VERSION 5.7 ;
BUSBITCHARS "[]" ;
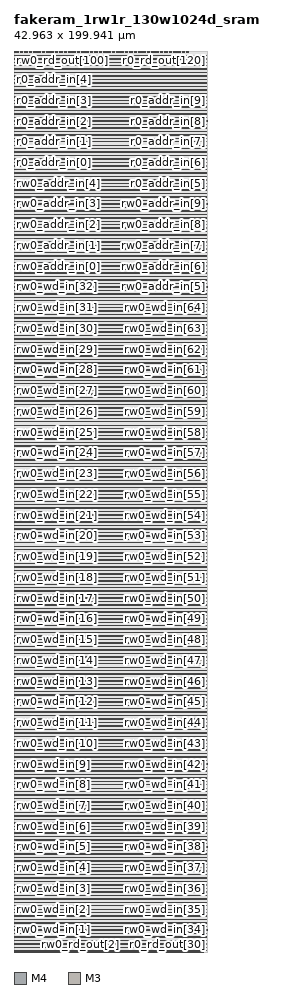
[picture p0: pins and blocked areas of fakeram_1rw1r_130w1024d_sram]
MACRO fakeram_1rw1r_130w1024d_sram
  FOREIGN fakeram_1rw1r_130w1024d_sram 0 0 ;
  SYMMETRY X Y R90 ;
  SIZE 42.963 BY 199.941 ;
  CLASS BLOCK ;
  PIN rw0_wd_in[0]
    DIRECTION INPUT ;
    USE SIGNAL ;
    SHAPE ABUTMENT ;
    PORT
      LAYER M4 ;
      RECT 0.000 0.276 0.072 0.300 ;
    END
  END rw0_wd_in[0]
  PIN rw0_wd_in[1]
    DIRECTION INPUT ;
    USE SIGNAL ;
    SHAPE ABUTMENT ;
    PORT
      LAYER M4 ;
      RECT 0.000 4.884 0.072 4.908 ;
    END
  END rw0_wd_in[1]
  PIN rw0_wd_in[2]
    DIRECTION INPUT ;
    USE SIGNAL ;
    SHAPE ABUTMENT ;
    PORT
      LAYER M4 ;
      RECT 0.000 9.492 0.072 9.516 ;
    END
  END rw0_wd_in[2]
  PIN rw0_wd_in[3]
    DIRECTION INPUT ;
    USE SIGNAL ;
    SHAPE ABUTMENT ;
    PORT
      LAYER M4 ;
      RECT 0.000 14.100 0.072 14.124 ;
    END
  END rw0_wd_in[3]
  PIN rw0_wd_in[4]
    DIRECTION INPUT ;
    USE SIGNAL ;
    SHAPE ABUTMENT ;
    PORT
      LAYER M4 ;
      RECT 0.000 18.708 0.072 18.732 ;
    END
  END rw0_wd_in[4]
  PIN rw0_wd_in[5]
    DIRECTION INPUT ;
    USE SIGNAL ;
    SHAPE ABUTMENT ;
    PORT
      LAYER M4 ;
      RECT 0.000 23.316 0.072 23.340 ;
    END
  END rw0_wd_in[5]
  PIN rw0_wd_in[6]
    DIRECTION INPUT ;
    USE SIGNAL ;
    SHAPE ABUTMENT ;
    PORT
      LAYER M4 ;
      RECT 0.000 27.924 0.072 27.948 ;
    END
  END rw0_wd_in[6]
  PIN rw0_wd_in[7]
    DIRECTION INPUT ;
    USE SIGNAL ;
    SHAPE ABUTMENT ;
    PORT
      LAYER M4 ;
      RECT 0.000 32.532 0.072 32.556 ;
    END
  END rw0_wd_in[7]
  PIN rw0_wd_in[8]
    DIRECTION INPUT ;
    USE SIGNAL ;
    SHAPE ABUTMENT ;
    PORT
      LAYER M4 ;
      RECT 0.000 37.140 0.072 37.164 ;
    END
  END rw0_wd_in[8]
  PIN rw0_wd_in[9]
    DIRECTION INPUT ;
    USE SIGNAL ;
    SHAPE ABUTMENT ;
    PORT
      LAYER M4 ;
      RECT 0.000 41.748 0.072 41.772 ;
    END
  END rw0_wd_in[9]
  PIN rw0_wd_in[10]
    DIRECTION INPUT ;
    USE SIGNAL ;
    SHAPE ABUTMENT ;
    PORT
      LAYER M4 ;
      RECT 0.000 46.356 0.072 46.380 ;
    END
  END rw0_wd_in[10]
  PIN rw0_wd_in[11]
    DIRECTION INPUT ;
    USE SIGNAL ;
    SHAPE ABUTMENT ;
    PORT
      LAYER M4 ;
      RECT 0.000 50.964 0.072 50.988 ;
    END
  END rw0_wd_in[11]
  PIN rw0_wd_in[12]
    DIRECTION INPUT ;
    USE SIGNAL ;
    SHAPE ABUTMENT ;
    PORT
      LAYER M4 ;
      RECT 0.000 55.572 0.072 55.596 ;
    END
  END rw0_wd_in[12]
  PIN rw0_wd_in[13]
    DIRECTION INPUT ;
    USE SIGNAL ;
    SHAPE ABUTMENT ;
    PORT
      LAYER M4 ;
      RECT 0.000 60.180 0.072 60.204 ;
    END
  END rw0_wd_in[13]
  PIN rw0_wd_in[14]
    DIRECTION INPUT ;
    USE SIGNAL ;
    SHAPE ABUTMENT ;
    PORT
      LAYER M4 ;
      RECT 0.000 64.788 0.072 64.812 ;
    END
  END rw0_wd_in[14]
  PIN rw0_wd_in[15]
    DIRECTION INPUT ;
    USE SIGNAL ;
    SHAPE ABUTMENT ;
    PORT
      LAYER M4 ;
      RECT 0.000 69.396 0.072 69.420 ;
    END
  END rw0_wd_in[15]
  PIN rw0_wd_in[16]
    DIRECTION INPUT ;
    USE SIGNAL ;
    SHAPE ABUTMENT ;
    PORT
      LAYER M4 ;
      RECT 0.000 74.004 0.072 74.028 ;
    END
  END rw0_wd_in[16]
  PIN rw0_wd_in[17]
    DIRECTION INPUT ;
    USE SIGNAL ;
    SHAPE ABUTMENT ;
    PORT
      LAYER M4 ;
      RECT 0.000 78.612 0.072 78.636 ;
    END
  END rw0_wd_in[17]
  PIN rw0_wd_in[18]
    DIRECTION INPUT ;
    USE SIGNAL ;
    SHAPE ABUTMENT ;
    PORT
      LAYER M4 ;
      RECT 0.000 83.220 0.072 83.244 ;
    END
  END rw0_wd_in[18]
  PIN rw0_wd_in[19]
    DIRECTION INPUT ;
    USE SIGNAL ;
    SHAPE ABUTMENT ;
    PORT
      LAYER M4 ;
      RECT 0.000 87.828 0.072 87.852 ;
    END
  END rw0_wd_in[19]
  PIN rw0_wd_in[20]
    DIRECTION INPUT ;
    USE SIGNAL ;
    SHAPE ABUTMENT ;
    PORT
      LAYER M4 ;
      RECT 0.000 92.436 0.072 92.460 ;
    END
  END rw0_wd_in[20]
  PIN rw0_wd_in[21]
    DIRECTION INPUT ;
    USE SIGNAL ;
    SHAPE ABUTMENT ;
    PORT
      LAYER M4 ;
      RECT 0.000 97.044 0.072 97.068 ;
    END
  END rw0_wd_in[21]
  PIN rw0_wd_in[22]
    DIRECTION INPUT ;
    USE SIGNAL ;
    SHAPE ABUTMENT ;
    PORT
      LAYER M4 ;
      RECT 0.000 101.652 0.072 101.676 ;
    END
  END rw0_wd_in[22]
  PIN rw0_wd_in[23]
    DIRECTION INPUT ;
    USE SIGNAL ;
    SHAPE ABUTMENT ;
    PORT
      LAYER M4 ;
      RECT 0.000 106.260 0.072 106.284 ;
    END
  END rw0_wd_in[23]
  PIN rw0_wd_in[24]
    DIRECTION INPUT ;
    USE SIGNAL ;
    SHAPE ABUTMENT ;
    PORT
      LAYER M4 ;
      RECT 0.000 110.868 0.072 110.892 ;
    END
  END rw0_wd_in[24]
  PIN rw0_wd_in[25]
    DIRECTION INPUT ;
    USE SIGNAL ;
    SHAPE ABUTMENT ;
    PORT
      LAYER M4 ;
      RECT 0.000 115.476 0.072 115.500 ;
    END
  END rw0_wd_in[25]
  PIN rw0_wd_in[26]
    DIRECTION INPUT ;
    USE SIGNAL ;
    SHAPE ABUTMENT ;
    PORT
      LAYER M4 ;
      RECT 0.000 120.084 0.072 120.108 ;
    END
  END rw0_wd_in[26]
  PIN rw0_wd_in[27]
    DIRECTION INPUT ;
    USE SIGNAL ;
    SHAPE ABUTMENT ;
    PORT
      LAYER M4 ;
      RECT 0.000 124.692 0.072 124.716 ;
    END
  END rw0_wd_in[27]
  PIN rw0_wd_in[28]
    DIRECTION INPUT ;
    USE SIGNAL ;
    SHAPE ABUTMENT ;
    PORT
      LAYER M4 ;
      RECT 0.000 129.300 0.072 129.324 ;
    END
  END rw0_wd_in[28]
  PIN rw0_wd_in[29]
    DIRECTION INPUT ;
    USE SIGNAL ;
    SHAPE ABUTMENT ;
    PORT
      LAYER M4 ;
      RECT 0.000 133.908 0.072 133.932 ;
    END
  END rw0_wd_in[29]
  PIN rw0_wd_in[30]
    DIRECTION INPUT ;
    USE SIGNAL ;
    SHAPE ABUTMENT ;
    PORT
      LAYER M4 ;
      RECT 0.000 138.516 0.072 138.540 ;
    END
  END rw0_wd_in[30]
  PIN rw0_wd_in[31]
    DIRECTION INPUT ;
    USE SIGNAL ;
    SHAPE ABUTMENT ;
    PORT
      LAYER M4 ;
      RECT 0.000 143.124 0.072 143.148 ;
    END
  END rw0_wd_in[31]
  PIN rw0_wd_in[32]
    DIRECTION INPUT ;
    USE SIGNAL ;
    SHAPE ABUTMENT ;
    PORT
      LAYER M4 ;
      RECT 0.000 147.732 0.072 147.756 ;
    END
  END rw0_wd_in[32]
  PIN rw0_wd_in[33]
    DIRECTION INPUT ;
    USE SIGNAL ;
    SHAPE ABUTMENT ;
    PORT
      LAYER M4 ;
      RECT 42.891 0.276 42.963 0.300 ;
    END
  END rw0_wd_in[33]
  PIN rw0_wd_in[34]
    DIRECTION INPUT ;
    USE SIGNAL ;
    SHAPE ABUTMENT ;
    PORT
      LAYER M4 ;
      RECT 42.891 4.884 42.963 4.908 ;
    END
  END rw0_wd_in[34]
  PIN rw0_wd_in[35]
    DIRECTION INPUT ;
    USE SIGNAL ;
    SHAPE ABUTMENT ;
    PORT
      LAYER M4 ;
      RECT 42.891 9.492 42.963 9.516 ;
    END
  END rw0_wd_in[35]
  PIN rw0_wd_in[36]
    DIRECTION INPUT ;
    USE SIGNAL ;
    SHAPE ABUTMENT ;
    PORT
      LAYER M4 ;
      RECT 42.891 14.100 42.963 14.124 ;
    END
  END rw0_wd_in[36]
  PIN rw0_wd_in[37]
    DIRECTION INPUT ;
    USE SIGNAL ;
    SHAPE ABUTMENT ;
    PORT
      LAYER M4 ;
      RECT 42.891 18.708 42.963 18.732 ;
    END
  END rw0_wd_in[37]
  PIN rw0_wd_in[38]
    DIRECTION INPUT ;
    USE SIGNAL ;
    SHAPE ABUTMENT ;
    PORT
      LAYER M4 ;
      RECT 42.891 23.316 42.963 23.340 ;
    END
  END rw0_wd_in[38]
  PIN rw0_wd_in[39]
    DIRECTION INPUT ;
    USE SIGNAL ;
    SHAPE ABUTMENT ;
    PORT
      LAYER M4 ;
      RECT 42.891 27.924 42.963 27.948 ;
    END
  END rw0_wd_in[39]
  PIN rw0_wd_in[40]
    DIRECTION INPUT ;
    USE SIGNAL ;
    SHAPE ABUTMENT ;
    PORT
      LAYER M4 ;
      RECT 42.891 32.532 42.963 32.556 ;
    END
  END rw0_wd_in[40]
  PIN rw0_wd_in[41]
    DIRECTION INPUT ;
    USE SIGNAL ;
    SHAPE ABUTMENT ;
    PORT
      LAYER M4 ;
      RECT 42.891 37.140 42.963 37.164 ;
    END
  END rw0_wd_in[41]
  PIN rw0_wd_in[42]
    DIRECTION INPUT ;
    USE SIGNAL ;
    SHAPE ABUTMENT ;
    PORT
      LAYER M4 ;
      RECT 42.891 41.748 42.963 41.772 ;
    END
  END rw0_wd_in[42]
  PIN rw0_wd_in[43]
    DIRECTION INPUT ;
    USE SIGNAL ;
    SHAPE ABUTMENT ;
    PORT
      LAYER M4 ;
      RECT 42.891 46.356 42.963 46.380 ;
    END
  END rw0_wd_in[43]
  PIN rw0_wd_in[44]
    DIRECTION INPUT ;
    USE SIGNAL ;
    SHAPE ABUTMENT ;
    PORT
      LAYER M4 ;
      RECT 42.891 50.964 42.963 50.988 ;
    END
  END rw0_wd_in[44]
  PIN rw0_wd_in[45]
    DIRECTION INPUT ;
    USE SIGNAL ;
    SHAPE ABUTMENT ;
    PORT
      LAYER M4 ;
      RECT 42.891 55.572 42.963 55.596 ;
    END
  END rw0_wd_in[45]
  PIN rw0_wd_in[46]
    DIRECTION INPUT ;
    USE SIGNAL ;
    SHAPE ABUTMENT ;
    PORT
      LAYER M4 ;
      RECT 42.891 60.180 42.963 60.204 ;
    END
  END rw0_wd_in[46]
  PIN rw0_wd_in[47]
    DIRECTION INPUT ;
    USE SIGNAL ;
    SHAPE ABUTMENT ;
    PORT
      LAYER M4 ;
      RECT 42.891 64.788 42.963 64.812 ;
    END
  END rw0_wd_in[47]
  PIN rw0_wd_in[48]
    DIRECTION INPUT ;
    USE SIGNAL ;
    SHAPE ABUTMENT ;
    PORT
      LAYER M4 ;
      RECT 42.891 69.396 42.963 69.420 ;
    END
  END rw0_wd_in[48]
  PIN rw0_wd_in[49]
    DIRECTION INPUT ;
    USE SIGNAL ;
    SHAPE ABUTMENT ;
    PORT
      LAYER M4 ;
      RECT 42.891 74.004 42.963 74.028 ;
    END
  END rw0_wd_in[49]
  PIN rw0_wd_in[50]
    DIRECTION INPUT ;
    USE SIGNAL ;
    SHAPE ABUTMENT ;
    PORT
      LAYER M4 ;
      RECT 42.891 78.612 42.963 78.636 ;
    END
  END rw0_wd_in[50]
  PIN rw0_wd_in[51]
    DIRECTION INPUT ;
    USE SIGNAL ;
    SHAPE ABUTMENT ;
    PORT
      LAYER M4 ;
      RECT 42.891 83.220 42.963 83.244 ;
    END
  END rw0_wd_in[51]
  PIN rw0_wd_in[52]
    DIRECTION INPUT ;
    USE SIGNAL ;
    SHAPE ABUTMENT ;
    PORT
      LAYER M4 ;
      RECT 42.891 87.828 42.963 87.852 ;
    END
  END rw0_wd_in[52]
  PIN rw0_wd_in[53]
    DIRECTION INPUT ;
    USE SIGNAL ;
    SHAPE ABUTMENT ;
    PORT
      LAYER M4 ;
      RECT 42.891 92.436 42.963 92.460 ;
    END
  END rw0_wd_in[53]
  PIN rw0_wd_in[54]
    DIRECTION INPUT ;
    USE SIGNAL ;
    SHAPE ABUTMENT ;
    PORT
      LAYER M4 ;
      RECT 42.891 97.044 42.963 97.068 ;
    END
  END rw0_wd_in[54]
  PIN rw0_wd_in[55]
    DIRECTION INPUT ;
    USE SIGNAL ;
    SHAPE ABUTMENT ;
    PORT
      LAYER M4 ;
      RECT 42.891 101.652 42.963 101.676 ;
    END
  END rw0_wd_in[55]
  PIN rw0_wd_in[56]
    DIRECTION INPUT ;
    USE SIGNAL ;
    SHAPE ABUTMENT ;
    PORT
      LAYER M4 ;
      RECT 42.891 106.260 42.963 106.284 ;
    END
  END rw0_wd_in[56]
  PIN rw0_wd_in[57]
    DIRECTION INPUT ;
    USE SIGNAL ;
    SHAPE ABUTMENT ;
    PORT
      LAYER M4 ;
      RECT 42.891 110.868 42.963 110.892 ;
    END
  END rw0_wd_in[57]
  PIN rw0_wd_in[58]
    DIRECTION INPUT ;
    USE SIGNAL ;
    SHAPE ABUTMENT ;
    PORT
      LAYER M4 ;
      RECT 42.891 115.476 42.963 115.500 ;
    END
  END rw0_wd_in[58]
  PIN rw0_wd_in[59]
    DIRECTION INPUT ;
    USE SIGNAL ;
    SHAPE ABUTMENT ;
    PORT
      LAYER M4 ;
      RECT 42.891 120.084 42.963 120.108 ;
    END
  END rw0_wd_in[59]
  PIN rw0_wd_in[60]
    DIRECTION INPUT ;
    USE SIGNAL ;
    SHAPE ABUTMENT ;
    PORT
      LAYER M4 ;
      RECT 42.891 124.692 42.963 124.716 ;
    END
  END rw0_wd_in[60]
  PIN rw0_wd_in[61]
    DIRECTION INPUT ;
    USE SIGNAL ;
    SHAPE ABUTMENT ;
    PORT
      LAYER M4 ;
      RECT 42.891 129.300 42.963 129.324 ;
    END
  END rw0_wd_in[61]
  PIN rw0_wd_in[62]
    DIRECTION INPUT ;
    USE SIGNAL ;
    SHAPE ABUTMENT ;
    PORT
      LAYER M4 ;
      RECT 42.891 133.908 42.963 133.932 ;
    END
  END rw0_wd_in[62]
  PIN rw0_wd_in[63]
    DIRECTION INPUT ;
    USE SIGNAL ;
    SHAPE ABUTMENT ;
    PORT
      LAYER M4 ;
      RECT 42.891 138.516 42.963 138.540 ;
    END
  END rw0_wd_in[63]
  PIN rw0_wd_in[64]
    DIRECTION INPUT ;
    USE SIGNAL ;
    SHAPE ABUTMENT ;
    PORT
      LAYER M4 ;
      RECT 42.891 143.124 42.963 143.148 ;
    END
  END rw0_wd_in[64]
  PIN rw0_wd_in[65]
    DIRECTION OUTPUT ;
    USE SIGNAL ;
    SHAPE ABUTMENT ;
    PORT
      LAYER M3 ;
      RECT 0.207 0.000 0.225 0.054 ;
    END
  END rw0_wd_in[65]
  PIN rw0_wd_in[66]
    DIRECTION OUTPUT ;
    USE SIGNAL ;
    SHAPE ABUTMENT ;
    PORT
      LAYER M3 ;
      RECT 0.423 0.000 0.441 0.054 ;
    END
  END rw0_wd_in[66]
  PIN rw0_wd_in[67]
    DIRECTION OUTPUT ;
    USE SIGNAL ;
    SHAPE ABUTMENT ;
    PORT
      LAYER M3 ;
      RECT 0.639 0.000 0.657 0.054 ;
    END
  END rw0_wd_in[67]
  PIN rw0_wd_in[68]
    DIRECTION OUTPUT ;
    USE SIGNAL ;
    SHAPE ABUTMENT ;
    PORT
      LAYER M3 ;
      RECT 0.855 0.000 0.873 0.054 ;
    END
  END rw0_wd_in[68]
  PIN rw0_wd_in[69]
    DIRECTION OUTPUT ;
    USE SIGNAL ;
    SHAPE ABUTMENT ;
    PORT
      LAYER M3 ;
      RECT 1.071 0.000 1.089 0.054 ;
    END
  END rw0_wd_in[69]
  PIN rw0_wd_in[70]
    DIRECTION OUTPUT ;
    USE SIGNAL ;
    SHAPE ABUTMENT ;
    PORT
      LAYER M3 ;
      RECT 1.287 0.000 1.305 0.054 ;
    END
  END rw0_wd_in[70]
  PIN rw0_wd_in[71]
    DIRECTION OUTPUT ;
    USE SIGNAL ;
    SHAPE ABUTMENT ;
    PORT
      LAYER M3 ;
      RECT 1.503 0.000 1.521 0.054 ;
    END
  END rw0_wd_in[71]
  PIN rw0_wd_in[72]
    DIRECTION OUTPUT ;
    USE SIGNAL ;
    SHAPE ABUTMENT ;
    PORT
      LAYER M3 ;
      RECT 1.719 0.000 1.737 0.054 ;
    END
  END rw0_wd_in[72]
  PIN rw0_wd_in[73]
    DIRECTION OUTPUT ;
    USE SIGNAL ;
    SHAPE ABUTMENT ;
    PORT
      LAYER M3 ;
      RECT 1.935 0.000 1.953 0.054 ;
    END
  END rw0_wd_in[73]
  PIN rw0_wd_in[74]
    DIRECTION OUTPUT ;
    USE SIGNAL ;
    SHAPE ABUTMENT ;
    PORT
      LAYER M3 ;
      RECT 2.151 0.000 2.169 0.054 ;
    END
  END rw0_wd_in[74]
  PIN rw0_wd_in[75]
    DIRECTION OUTPUT ;
    USE SIGNAL ;
    SHAPE ABUTMENT ;
    PORT
      LAYER M3 ;
      RECT 2.367 0.000 2.385 0.054 ;
    END
  END rw0_wd_in[75]
  PIN rw0_wd_in[76]
    DIRECTION OUTPUT ;
    USE SIGNAL ;
    SHAPE ABUTMENT ;
    PORT
      LAYER M3 ;
      RECT 2.583 0.000 2.601 0.054 ;
    END
  END rw0_wd_in[76]
  PIN rw0_wd_in[77]
    DIRECTION OUTPUT ;
    USE SIGNAL ;
    SHAPE ABUTMENT ;
    PORT
      LAYER M3 ;
      RECT 2.799 0.000 2.817 0.054 ;
    END
  END rw0_wd_in[77]
  PIN rw0_wd_in[78]
    DIRECTION OUTPUT ;
    USE SIGNAL ;
    SHAPE ABUTMENT ;
    PORT
      LAYER M3 ;
      RECT 3.015 0.000 3.033 0.054 ;
    END
  END rw0_wd_in[78]
  PIN rw0_wd_in[79]
    DIRECTION OUTPUT ;
    USE SIGNAL ;
    SHAPE ABUTMENT ;
    PORT
      LAYER M3 ;
      RECT 3.231 0.000 3.249 0.054 ;
    END
  END rw0_wd_in[79]
  PIN rw0_wd_in[80]
    DIRECTION OUTPUT ;
    USE SIGNAL ;
    SHAPE ABUTMENT ;
    PORT
      LAYER M3 ;
      RECT 3.447 0.000 3.465 0.054 ;
    END
  END rw0_wd_in[80]
  PIN rw0_wd_in[81]
    DIRECTION OUTPUT ;
    USE SIGNAL ;
    SHAPE ABUTMENT ;
    PORT
      LAYER M3 ;
      RECT 3.663 0.000 3.681 0.054 ;
    END
  END rw0_wd_in[81]
  PIN rw0_wd_in[82]
    DIRECTION OUTPUT ;
    USE SIGNAL ;
    SHAPE ABUTMENT ;
    PORT
      LAYER M3 ;
      RECT 3.879 0.000 3.897 0.054 ;
    END
  END rw0_wd_in[82]
  PIN rw0_wd_in[83]
    DIRECTION OUTPUT ;
    USE SIGNAL ;
    SHAPE ABUTMENT ;
    PORT
      LAYER M3 ;
      RECT 4.095 0.000 4.113 0.054 ;
    END
  END rw0_wd_in[83]
  PIN rw0_wd_in[84]
    DIRECTION OUTPUT ;
    USE SIGNAL ;
    SHAPE ABUTMENT ;
    PORT
      LAYER M3 ;
      RECT 4.311 0.000 4.329 0.054 ;
    END
  END rw0_wd_in[84]
  PIN rw0_wd_in[85]
    DIRECTION OUTPUT ;
    USE SIGNAL ;
    SHAPE ABUTMENT ;
    PORT
      LAYER M3 ;
      RECT 4.527 0.000 4.545 0.054 ;
    END
  END rw0_wd_in[85]
  PIN rw0_wd_in[86]
    DIRECTION OUTPUT ;
    USE SIGNAL ;
    SHAPE ABUTMENT ;
    PORT
      LAYER M3 ;
      RECT 4.743 0.000 4.761 0.054 ;
    END
  END rw0_wd_in[86]
  PIN rw0_wd_in[87]
    DIRECTION OUTPUT ;
    USE SIGNAL ;
    SHAPE ABUTMENT ;
    PORT
      LAYER M3 ;
      RECT 4.959 0.000 4.977 0.054 ;
    END
  END rw0_wd_in[87]
  PIN rw0_wd_in[88]
    DIRECTION OUTPUT ;
    USE SIGNAL ;
    SHAPE ABUTMENT ;
    PORT
      LAYER M3 ;
      RECT 5.175 0.000 5.193 0.054 ;
    END
  END rw0_wd_in[88]
  PIN rw0_wd_in[89]
    DIRECTION OUTPUT ;
    USE SIGNAL ;
    SHAPE ABUTMENT ;
    PORT
      LAYER M3 ;
      RECT 5.391 0.000 5.409 0.054 ;
    END
  END rw0_wd_in[89]
  PIN rw0_wd_in[90]
    DIRECTION OUTPUT ;
    USE SIGNAL ;
    SHAPE ABUTMENT ;
    PORT
      LAYER M3 ;
      RECT 5.607 0.000 5.625 0.054 ;
    END
  END rw0_wd_in[90]
  PIN rw0_wd_in[91]
    DIRECTION OUTPUT ;
    USE SIGNAL ;
    SHAPE ABUTMENT ;
    PORT
      LAYER M3 ;
      RECT 5.823 0.000 5.841 0.054 ;
    END
  END rw0_wd_in[91]
  PIN rw0_wd_in[92]
    DIRECTION OUTPUT ;
    USE SIGNAL ;
    SHAPE ABUTMENT ;
    PORT
      LAYER M3 ;
      RECT 6.039 0.000 6.057 0.054 ;
    END
  END rw0_wd_in[92]
  PIN rw0_wd_in[93]
    DIRECTION OUTPUT ;
    USE SIGNAL ;
    SHAPE ABUTMENT ;
    PORT
      LAYER M3 ;
      RECT 6.255 0.000 6.273 0.054 ;
    END
  END rw0_wd_in[93]
  PIN rw0_wd_in[94]
    DIRECTION OUTPUT ;
    USE SIGNAL ;
    SHAPE ABUTMENT ;
    PORT
      LAYER M3 ;
      RECT 6.471 0.000 6.489 0.054 ;
    END
  END rw0_wd_in[94]
  PIN rw0_wd_in[95]
    DIRECTION OUTPUT ;
    USE SIGNAL ;
    SHAPE ABUTMENT ;
    PORT
      LAYER M3 ;
      RECT 6.687 0.000 6.705 0.054 ;
    END
  END rw0_wd_in[95]
  PIN rw0_wd_in[96]
    DIRECTION OUTPUT ;
    USE SIGNAL ;
    SHAPE ABUTMENT ;
    PORT
      LAYER M3 ;
      RECT 6.903 0.000 6.921 0.054 ;
    END
  END rw0_wd_in[96]
  PIN rw0_wd_in[97]
    DIRECTION OUTPUT ;
    USE SIGNAL ;
    SHAPE ABUTMENT ;
    PORT
      LAYER M3 ;
      RECT 7.119 0.000 7.137 0.054 ;
    END
  END rw0_wd_in[97]
  PIN rw0_wd_in[98]
    DIRECTION OUTPUT ;
    USE SIGNAL ;
    SHAPE ABUTMENT ;
    PORT
      LAYER M3 ;
      RECT 7.335 0.000 7.353 0.054 ;
    END
  END rw0_wd_in[98]
  PIN rw0_wd_in[99]
    DIRECTION OUTPUT ;
    USE SIGNAL ;
    SHAPE ABUTMENT ;
    PORT
      LAYER M3 ;
      RECT 7.551 0.000 7.569 0.054 ;
    END
  END rw0_wd_in[99]
  PIN rw0_wd_in[100]
    DIRECTION OUTPUT ;
    USE SIGNAL ;
    SHAPE ABUTMENT ;
    PORT
      LAYER M3 ;
      RECT 7.767 0.000 7.785 0.054 ;
    END
  END rw0_wd_in[100]
  PIN rw0_wd_in[101]
    DIRECTION OUTPUT ;
    USE SIGNAL ;
    SHAPE ABUTMENT ;
    PORT
      LAYER M3 ;
      RECT 7.983 0.000 8.001 0.054 ;
    END
  END rw0_wd_in[101]
  PIN rw0_wd_in[102]
    DIRECTION OUTPUT ;
    USE SIGNAL ;
    SHAPE ABUTMENT ;
    PORT
      LAYER M3 ;
      RECT 8.199 0.000 8.217 0.054 ;
    END
  END rw0_wd_in[102]
  PIN rw0_wd_in[103]
    DIRECTION OUTPUT ;
    USE SIGNAL ;
    SHAPE ABUTMENT ;
    PORT
      LAYER M3 ;
      RECT 8.415 0.000 8.433 0.054 ;
    END
  END rw0_wd_in[103]
  PIN rw0_wd_in[104]
    DIRECTION OUTPUT ;
    USE SIGNAL ;
    SHAPE ABUTMENT ;
    PORT
      LAYER M3 ;
      RECT 8.631 0.000 8.649 0.054 ;
    END
  END rw0_wd_in[104]
  PIN rw0_wd_in[105]
    DIRECTION OUTPUT ;
    USE SIGNAL ;
    SHAPE ABUTMENT ;
    PORT
      LAYER M3 ;
      RECT 8.847 0.000 8.865 0.054 ;
    END
  END rw0_wd_in[105]
  PIN rw0_wd_in[106]
    DIRECTION OUTPUT ;
    USE SIGNAL ;
    SHAPE ABUTMENT ;
    PORT
      LAYER M3 ;
      RECT 9.063 0.000 9.081 0.054 ;
    END
  END rw0_wd_in[106]
  PIN rw0_wd_in[107]
    DIRECTION OUTPUT ;
    USE SIGNAL ;
    SHAPE ABUTMENT ;
    PORT
      LAYER M3 ;
      RECT 9.279 0.000 9.297 0.054 ;
    END
  END rw0_wd_in[107]
  PIN rw0_wd_in[108]
    DIRECTION OUTPUT ;
    USE SIGNAL ;
    SHAPE ABUTMENT ;
    PORT
      LAYER M3 ;
      RECT 9.495 0.000 9.513 0.054 ;
    END
  END rw0_wd_in[108]
  PIN rw0_wd_in[109]
    DIRECTION OUTPUT ;
    USE SIGNAL ;
    SHAPE ABUTMENT ;
    PORT
      LAYER M3 ;
      RECT 9.711 0.000 9.729 0.054 ;
    END
  END rw0_wd_in[109]
  PIN rw0_wd_in[110]
    DIRECTION OUTPUT ;
    USE SIGNAL ;
    SHAPE ABUTMENT ;
    PORT
      LAYER M3 ;
      RECT 9.927 0.000 9.945 0.054 ;
    END
  END rw0_wd_in[110]
  PIN rw0_wd_in[111]
    DIRECTION OUTPUT ;
    USE SIGNAL ;
    SHAPE ABUTMENT ;
    PORT
      LAYER M3 ;
      RECT 10.143 0.000 10.161 0.054 ;
    END
  END rw0_wd_in[111]
  PIN rw0_wd_in[112]
    DIRECTION OUTPUT ;
    USE SIGNAL ;
    SHAPE ABUTMENT ;
    PORT
      LAYER M3 ;
      RECT 10.359 0.000 10.377 0.054 ;
    END
  END rw0_wd_in[112]
  PIN rw0_wd_in[113]
    DIRECTION OUTPUT ;
    USE SIGNAL ;
    SHAPE ABUTMENT ;
    PORT
      LAYER M3 ;
      RECT 10.575 0.000 10.593 0.054 ;
    END
  END rw0_wd_in[113]
  PIN rw0_wd_in[114]
    DIRECTION OUTPUT ;
    USE SIGNAL ;
    SHAPE ABUTMENT ;
    PORT
      LAYER M3 ;
      RECT 10.791 0.000 10.809 0.054 ;
    END
  END rw0_wd_in[114]
  PIN rw0_wd_in[115]
    DIRECTION OUTPUT ;
    USE SIGNAL ;
    SHAPE ABUTMENT ;
    PORT
      LAYER M3 ;
      RECT 11.007 0.000 11.025 0.054 ;
    END
  END rw0_wd_in[115]
  PIN rw0_wd_in[116]
    DIRECTION OUTPUT ;
    USE SIGNAL ;
    SHAPE ABUTMENT ;
    PORT
      LAYER M3 ;
      RECT 11.223 0.000 11.241 0.054 ;
    END
  END rw0_wd_in[116]
  PIN rw0_wd_in[117]
    DIRECTION OUTPUT ;
    USE SIGNAL ;
    SHAPE ABUTMENT ;
    PORT
      LAYER M3 ;
      RECT 11.439 0.000 11.457 0.054 ;
    END
  END rw0_wd_in[117]
  PIN rw0_wd_in[118]
    DIRECTION OUTPUT ;
    USE SIGNAL ;
    SHAPE ABUTMENT ;
    PORT
      LAYER M3 ;
      RECT 11.655 0.000 11.673 0.054 ;
    END
  END rw0_wd_in[118]
  PIN rw0_wd_in[119]
    DIRECTION OUTPUT ;
    USE SIGNAL ;
    SHAPE ABUTMENT ;
    PORT
      LAYER M3 ;
      RECT 11.871 0.000 11.889 0.054 ;
    END
  END rw0_wd_in[119]
  PIN rw0_wd_in[120]
    DIRECTION OUTPUT ;
    USE SIGNAL ;
    SHAPE ABUTMENT ;
    PORT
      LAYER M3 ;
      RECT 12.087 0.000 12.105 0.054 ;
    END
  END rw0_wd_in[120]
  PIN rw0_wd_in[121]
    DIRECTION OUTPUT ;
    USE SIGNAL ;
    SHAPE ABUTMENT ;
    PORT
      LAYER M3 ;
      RECT 12.303 0.000 12.321 0.054 ;
    END
  END rw0_wd_in[121]
  PIN rw0_wd_in[122]
    DIRECTION OUTPUT ;
    USE SIGNAL ;
    SHAPE ABUTMENT ;
    PORT
      LAYER M3 ;
      RECT 12.519 0.000 12.537 0.054 ;
    END
  END rw0_wd_in[122]
  PIN rw0_wd_in[123]
    DIRECTION OUTPUT ;
    USE SIGNAL ;
    SHAPE ABUTMENT ;
    PORT
      LAYER M3 ;
      RECT 12.735 0.000 12.753 0.054 ;
    END
  END rw0_wd_in[123]
  PIN rw0_wd_in[124]
    DIRECTION OUTPUT ;
    USE SIGNAL ;
    SHAPE ABUTMENT ;
    PORT
      LAYER M3 ;
      RECT 12.951 0.000 12.969 0.054 ;
    END
  END rw0_wd_in[124]
  PIN rw0_wd_in[125]
    DIRECTION OUTPUT ;
    USE SIGNAL ;
    SHAPE ABUTMENT ;
    PORT
      LAYER M3 ;
      RECT 13.167 0.000 13.185 0.054 ;
    END
  END rw0_wd_in[125]
  PIN rw0_wd_in[126]
    DIRECTION OUTPUT ;
    USE SIGNAL ;
    SHAPE ABUTMENT ;
    PORT
      LAYER M3 ;
      RECT 13.383 0.000 13.401 0.054 ;
    END
  END rw0_wd_in[126]
  PIN rw0_wd_in[127]
    DIRECTION OUTPUT ;
    USE SIGNAL ;
    SHAPE ABUTMENT ;
    PORT
      LAYER M3 ;
      RECT 13.599 0.000 13.617 0.054 ;
    END
  END rw0_wd_in[127]
  PIN rw0_wd_in[128]
    DIRECTION OUTPUT ;
    USE SIGNAL ;
    SHAPE ABUTMENT ;
    PORT
      LAYER M3 ;
      RECT 13.815 0.000 13.833 0.054 ;
    END
  END rw0_wd_in[128]
  PIN rw0_wd_in[129]
    DIRECTION OUTPUT ;
    USE SIGNAL ;
    SHAPE ABUTMENT ;
    PORT
      LAYER M3 ;
      RECT 14.031 0.000 14.049 0.054 ;
    END
  END rw0_wd_in[129]
  PIN rw0_rd_out[0]
    DIRECTION OUTPUT ;
    USE SIGNAL ;
    SHAPE ABUTMENT ;
    PORT
      LAYER M3 ;
      RECT 14.247 0.000 14.265 0.054 ;
    END
  END rw0_rd_out[0]
  PIN rw0_rd_out[1]
    DIRECTION OUTPUT ;
    USE SIGNAL ;
    SHAPE ABUTMENT ;
    PORT
      LAYER M3 ;
      RECT 14.463 0.000 14.481 0.054 ;
    END
  END rw0_rd_out[1]
  PIN rw0_rd_out[2]
    DIRECTION OUTPUT ;
    USE SIGNAL ;
    SHAPE ABUTMENT ;
    PORT
      LAYER M3 ;
      RECT 14.679 0.000 14.697 0.054 ;
    END
  END rw0_rd_out[2]
  PIN rw0_rd_out[3]
    DIRECTION OUTPUT ;
    USE SIGNAL ;
    SHAPE ABUTMENT ;
    PORT
      LAYER M3 ;
      RECT 14.895 0.000 14.913 0.054 ;
    END
  END rw0_rd_out[3]
  PIN rw0_rd_out[4]
    DIRECTION OUTPUT ;
    USE SIGNAL ;
    SHAPE ABUTMENT ;
    PORT
      LAYER M3 ;
      RECT 15.111 0.000 15.129 0.054 ;
    END
  END rw0_rd_out[4]
  PIN rw0_rd_out[5]
    DIRECTION OUTPUT ;
    USE SIGNAL ;
    SHAPE ABUTMENT ;
    PORT
      LAYER M3 ;
      RECT 15.327 0.000 15.345 0.054 ;
    END
  END rw0_rd_out[5]
  PIN rw0_rd_out[6]
    DIRECTION OUTPUT ;
    USE SIGNAL ;
    SHAPE ABUTMENT ;
    PORT
      LAYER M3 ;
      RECT 15.543 0.000 15.561 0.054 ;
    END
  END rw0_rd_out[6]
  PIN rw0_rd_out[7]
    DIRECTION OUTPUT ;
    USE SIGNAL ;
    SHAPE ABUTMENT ;
    PORT
      LAYER M3 ;
      RECT 15.759 0.000 15.777 0.054 ;
    END
  END rw0_rd_out[7]
  PIN rw0_rd_out[8]
    DIRECTION OUTPUT ;
    USE SIGNAL ;
    SHAPE ABUTMENT ;
    PORT
      LAYER M3 ;
      RECT 15.975 0.000 15.993 0.054 ;
    END
  END rw0_rd_out[8]
  PIN rw0_rd_out[9]
    DIRECTION OUTPUT ;
    USE SIGNAL ;
    SHAPE ABUTMENT ;
    PORT
      LAYER M3 ;
      RECT 16.191 0.000 16.209 0.054 ;
    END
  END rw0_rd_out[9]
  PIN rw0_rd_out[10]
    DIRECTION OUTPUT ;
    USE SIGNAL ;
    SHAPE ABUTMENT ;
    PORT
      LAYER M3 ;
      RECT 16.407 0.000 16.425 0.054 ;
    END
  END rw0_rd_out[10]
  PIN rw0_rd_out[11]
    DIRECTION OUTPUT ;
    USE SIGNAL ;
    SHAPE ABUTMENT ;
    PORT
      LAYER M3 ;
      RECT 16.623 0.000 16.641 0.054 ;
    END
  END rw0_rd_out[11]
  PIN rw0_rd_out[12]
    DIRECTION OUTPUT ;
    USE SIGNAL ;
    SHAPE ABUTMENT ;
    PORT
      LAYER M3 ;
      RECT 16.839 0.000 16.857 0.054 ;
    END
  END rw0_rd_out[12]
  PIN rw0_rd_out[13]
    DIRECTION OUTPUT ;
    USE SIGNAL ;
    SHAPE ABUTMENT ;
    PORT
      LAYER M3 ;
      RECT 17.055 0.000 17.073 0.054 ;
    END
  END rw0_rd_out[13]
  PIN rw0_rd_out[14]
    DIRECTION OUTPUT ;
    USE SIGNAL ;
    SHAPE ABUTMENT ;
    PORT
      LAYER M3 ;
      RECT 17.271 0.000 17.289 0.054 ;
    END
  END rw0_rd_out[14]
  PIN rw0_rd_out[15]
    DIRECTION OUTPUT ;
    USE SIGNAL ;
    SHAPE ABUTMENT ;
    PORT
      LAYER M3 ;
      RECT 17.487 0.000 17.505 0.054 ;
    END
  END rw0_rd_out[15]
  PIN rw0_rd_out[16]
    DIRECTION OUTPUT ;
    USE SIGNAL ;
    SHAPE ABUTMENT ;
    PORT
      LAYER M3 ;
      RECT 17.703 0.000 17.721 0.054 ;
    END
  END rw0_rd_out[16]
  PIN rw0_rd_out[17]
    DIRECTION OUTPUT ;
    USE SIGNAL ;
    SHAPE ABUTMENT ;
    PORT
      LAYER M3 ;
      RECT 17.919 0.000 17.937 0.054 ;
    END
  END rw0_rd_out[17]
  PIN rw0_rd_out[18]
    DIRECTION OUTPUT ;
    USE SIGNAL ;
    SHAPE ABUTMENT ;
    PORT
      LAYER M3 ;
      RECT 18.135 0.000 18.153 0.054 ;
    END
  END rw0_rd_out[18]
  PIN rw0_rd_out[19]
    DIRECTION OUTPUT ;
    USE SIGNAL ;
    SHAPE ABUTMENT ;
    PORT
      LAYER M3 ;
      RECT 18.351 0.000 18.369 0.054 ;
    END
  END rw0_rd_out[19]
  PIN rw0_rd_out[20]
    DIRECTION OUTPUT ;
    USE SIGNAL ;
    SHAPE ABUTMENT ;
    PORT
      LAYER M3 ;
      RECT 18.567 0.000 18.585 0.054 ;
    END
  END rw0_rd_out[20]
  PIN rw0_rd_out[21]
    DIRECTION OUTPUT ;
    USE SIGNAL ;
    SHAPE ABUTMENT ;
    PORT
      LAYER M3 ;
      RECT 18.783 0.000 18.801 0.054 ;
    END
  END rw0_rd_out[21]
  PIN rw0_rd_out[22]
    DIRECTION OUTPUT ;
    USE SIGNAL ;
    SHAPE ABUTMENT ;
    PORT
      LAYER M3 ;
      RECT 18.999 0.000 19.017 0.054 ;
    END
  END rw0_rd_out[22]
  PIN rw0_rd_out[23]
    DIRECTION OUTPUT ;
    USE SIGNAL ;
    SHAPE ABUTMENT ;
    PORT
      LAYER M3 ;
      RECT 19.215 0.000 19.233 0.054 ;
    END
  END rw0_rd_out[23]
  PIN rw0_rd_out[24]
    DIRECTION OUTPUT ;
    USE SIGNAL ;
    SHAPE ABUTMENT ;
    PORT
      LAYER M3 ;
      RECT 19.431 0.000 19.449 0.054 ;
    END
  END rw0_rd_out[24]
  PIN rw0_rd_out[25]
    DIRECTION OUTPUT ;
    USE SIGNAL ;
    SHAPE ABUTMENT ;
    PORT
      LAYER M3 ;
      RECT 19.647 0.000 19.665 0.054 ;
    END
  END rw0_rd_out[25]
  PIN rw0_rd_out[26]
    DIRECTION OUTPUT ;
    USE SIGNAL ;
    SHAPE ABUTMENT ;
    PORT
      LAYER M3 ;
      RECT 19.863 0.000 19.881 0.054 ;
    END
  END rw0_rd_out[26]
  PIN rw0_rd_out[27]
    DIRECTION OUTPUT ;
    USE SIGNAL ;
    SHAPE ABUTMENT ;
    PORT
      LAYER M3 ;
      RECT 20.079 0.000 20.097 0.054 ;
    END
  END rw0_rd_out[27]
  PIN rw0_rd_out[28]
    DIRECTION OUTPUT ;
    USE SIGNAL ;
    SHAPE ABUTMENT ;
    PORT
      LAYER M3 ;
      RECT 20.295 0.000 20.313 0.054 ;
    END
  END rw0_rd_out[28]
  PIN rw0_rd_out[29]
    DIRECTION OUTPUT ;
    USE SIGNAL ;
    SHAPE ABUTMENT ;
    PORT
      LAYER M3 ;
      RECT 20.511 0.000 20.529 0.054 ;
    END
  END rw0_rd_out[29]
  PIN rw0_rd_out[30]
    DIRECTION OUTPUT ;
    USE SIGNAL ;
    SHAPE ABUTMENT ;
    PORT
      LAYER M3 ;
      RECT 20.727 0.000 20.745 0.054 ;
    END
  END rw0_rd_out[30]
  PIN rw0_rd_out[31]
    DIRECTION OUTPUT ;
    USE SIGNAL ;
    SHAPE ABUTMENT ;
    PORT
      LAYER M3 ;
      RECT 20.943 0.000 20.961 0.054 ;
    END
  END rw0_rd_out[31]
  PIN rw0_rd_out[32]
    DIRECTION OUTPUT ;
    USE SIGNAL ;
    SHAPE ABUTMENT ;
    PORT
      LAYER M3 ;
      RECT 21.159 0.000 21.177 0.054 ;
    END
  END rw0_rd_out[32]
  PIN rw0_rd_out[33]
    DIRECTION OUTPUT ;
    USE SIGNAL ;
    SHAPE ABUTMENT ;
    PORT
      LAYER M3 ;
      RECT 21.375 0.000 21.393 0.054 ;
    END
  END rw0_rd_out[33]
  PIN rw0_rd_out[34]
    DIRECTION OUTPUT ;
    USE SIGNAL ;
    SHAPE ABUTMENT ;
    PORT
      LAYER M3 ;
      RECT 21.591 0.000 21.609 0.054 ;
    END
  END rw0_rd_out[34]
  PIN rw0_rd_out[35]
    DIRECTION OUTPUT ;
    USE SIGNAL ;
    SHAPE ABUTMENT ;
    PORT
      LAYER M3 ;
      RECT 21.807 0.000 21.825 0.054 ;
    END
  END rw0_rd_out[35]
  PIN rw0_rd_out[36]
    DIRECTION OUTPUT ;
    USE SIGNAL ;
    SHAPE ABUTMENT ;
    PORT
      LAYER M3 ;
      RECT 22.023 0.000 22.041 0.054 ;
    END
  END rw0_rd_out[36]
  PIN rw0_rd_out[37]
    DIRECTION OUTPUT ;
    USE SIGNAL ;
    SHAPE ABUTMENT ;
    PORT
      LAYER M3 ;
      RECT 22.239 0.000 22.257 0.054 ;
    END
  END rw0_rd_out[37]
  PIN rw0_rd_out[38]
    DIRECTION OUTPUT ;
    USE SIGNAL ;
    SHAPE ABUTMENT ;
    PORT
      LAYER M3 ;
      RECT 22.455 0.000 22.473 0.054 ;
    END
  END rw0_rd_out[38]
  PIN rw0_rd_out[39]
    DIRECTION OUTPUT ;
    USE SIGNAL ;
    SHAPE ABUTMENT ;
    PORT
      LAYER M3 ;
      RECT 22.671 0.000 22.689 0.054 ;
    END
  END rw0_rd_out[39]
  PIN rw0_rd_out[40]
    DIRECTION OUTPUT ;
    USE SIGNAL ;
    SHAPE ABUTMENT ;
    PORT
      LAYER M3 ;
      RECT 22.887 0.000 22.905 0.054 ;
    END
  END rw0_rd_out[40]
  PIN rw0_rd_out[41]
    DIRECTION OUTPUT ;
    USE SIGNAL ;
    SHAPE ABUTMENT ;
    PORT
      LAYER M3 ;
      RECT 23.103 0.000 23.121 0.054 ;
    END
  END rw0_rd_out[41]
  PIN rw0_rd_out[42]
    DIRECTION OUTPUT ;
    USE SIGNAL ;
    SHAPE ABUTMENT ;
    PORT
      LAYER M3 ;
      RECT 23.319 0.000 23.337 0.054 ;
    END
  END rw0_rd_out[42]
  PIN rw0_rd_out[43]
    DIRECTION OUTPUT ;
    USE SIGNAL ;
    SHAPE ABUTMENT ;
    PORT
      LAYER M3 ;
      RECT 23.535 0.000 23.553 0.054 ;
    END
  END rw0_rd_out[43]
  PIN rw0_rd_out[44]
    DIRECTION OUTPUT ;
    USE SIGNAL ;
    SHAPE ABUTMENT ;
    PORT
      LAYER M3 ;
      RECT 23.751 0.000 23.769 0.054 ;
    END
  END rw0_rd_out[44]
  PIN rw0_rd_out[45]
    DIRECTION OUTPUT ;
    USE SIGNAL ;
    SHAPE ABUTMENT ;
    PORT
      LAYER M3 ;
      RECT 23.967 0.000 23.985 0.054 ;
    END
  END rw0_rd_out[45]
  PIN rw0_rd_out[46]
    DIRECTION OUTPUT ;
    USE SIGNAL ;
    SHAPE ABUTMENT ;
    PORT
      LAYER M3 ;
      RECT 24.183 0.000 24.201 0.054 ;
    END
  END rw0_rd_out[46]
  PIN rw0_rd_out[47]
    DIRECTION OUTPUT ;
    USE SIGNAL ;
    SHAPE ABUTMENT ;
    PORT
      LAYER M3 ;
      RECT 24.399 0.000 24.417 0.054 ;
    END
  END rw0_rd_out[47]
  PIN rw0_rd_out[48]
    DIRECTION OUTPUT ;
    USE SIGNAL ;
    SHAPE ABUTMENT ;
    PORT
      LAYER M3 ;
      RECT 24.615 0.000 24.633 0.054 ;
    END
  END rw0_rd_out[48]
  PIN rw0_rd_out[49]
    DIRECTION OUTPUT ;
    USE SIGNAL ;
    SHAPE ABUTMENT ;
    PORT
      LAYER M3 ;
      RECT 24.831 0.000 24.849 0.054 ;
    END
  END rw0_rd_out[49]
  PIN rw0_rd_out[50]
    DIRECTION OUTPUT ;
    USE SIGNAL ;
    SHAPE ABUTMENT ;
    PORT
      LAYER M3 ;
      RECT 25.047 0.000 25.065 0.054 ;
    END
  END rw0_rd_out[50]
  PIN rw0_rd_out[51]
    DIRECTION OUTPUT ;
    USE SIGNAL ;
    SHAPE ABUTMENT ;
    PORT
      LAYER M3 ;
      RECT 25.263 0.000 25.281 0.054 ;
    END
  END rw0_rd_out[51]
  PIN rw0_rd_out[52]
    DIRECTION OUTPUT ;
    USE SIGNAL ;
    SHAPE ABUTMENT ;
    PORT
      LAYER M3 ;
      RECT 25.479 0.000 25.497 0.054 ;
    END
  END rw0_rd_out[52]
  PIN rw0_rd_out[53]
    DIRECTION OUTPUT ;
    USE SIGNAL ;
    SHAPE ABUTMENT ;
    PORT
      LAYER M3 ;
      RECT 25.695 0.000 25.713 0.054 ;
    END
  END rw0_rd_out[53]
  PIN rw0_rd_out[54]
    DIRECTION OUTPUT ;
    USE SIGNAL ;
    SHAPE ABUTMENT ;
    PORT
      LAYER M3 ;
      RECT 25.911 0.000 25.929 0.054 ;
    END
  END rw0_rd_out[54]
  PIN rw0_rd_out[55]
    DIRECTION OUTPUT ;
    USE SIGNAL ;
    SHAPE ABUTMENT ;
    PORT
      LAYER M3 ;
      RECT 26.127 0.000 26.145 0.054 ;
    END
  END rw0_rd_out[55]
  PIN rw0_rd_out[56]
    DIRECTION OUTPUT ;
    USE SIGNAL ;
    SHAPE ABUTMENT ;
    PORT
      LAYER M3 ;
      RECT 26.343 0.000 26.361 0.054 ;
    END
  END rw0_rd_out[56]
  PIN rw0_rd_out[57]
    DIRECTION OUTPUT ;
    USE SIGNAL ;
    SHAPE ABUTMENT ;
    PORT
      LAYER M3 ;
      RECT 26.559 0.000 26.577 0.054 ;
    END
  END rw0_rd_out[57]
  PIN rw0_rd_out[58]
    DIRECTION OUTPUT ;
    USE SIGNAL ;
    SHAPE ABUTMENT ;
    PORT
      LAYER M3 ;
      RECT 26.775 0.000 26.793 0.054 ;
    END
  END rw0_rd_out[58]
  PIN rw0_rd_out[59]
    DIRECTION OUTPUT ;
    USE SIGNAL ;
    SHAPE ABUTMENT ;
    PORT
      LAYER M3 ;
      RECT 26.991 0.000 27.009 0.054 ;
    END
  END rw0_rd_out[59]
  PIN rw0_rd_out[60]
    DIRECTION OUTPUT ;
    USE SIGNAL ;
    SHAPE ABUTMENT ;
    PORT
      LAYER M3 ;
      RECT 27.207 0.000 27.225 0.054 ;
    END
  END rw0_rd_out[60]
  PIN rw0_rd_out[61]
    DIRECTION OUTPUT ;
    USE SIGNAL ;
    SHAPE ABUTMENT ;
    PORT
      LAYER M3 ;
      RECT 27.423 0.000 27.441 0.054 ;
    END
  END rw0_rd_out[61]
  PIN rw0_rd_out[62]
    DIRECTION OUTPUT ;
    USE SIGNAL ;
    SHAPE ABUTMENT ;
    PORT
      LAYER M3 ;
      RECT 27.639 0.000 27.657 0.054 ;
    END
  END rw0_rd_out[62]
  PIN rw0_rd_out[63]
    DIRECTION OUTPUT ;
    USE SIGNAL ;
    SHAPE ABUTMENT ;
    PORT
      LAYER M3 ;
      RECT 27.855 0.000 27.873 0.054 ;
    END
  END rw0_rd_out[63]
  PIN rw0_rd_out[64]
    DIRECTION OUTPUT ;
    USE SIGNAL ;
    SHAPE ABUTMENT ;
    PORT
      LAYER M3 ;
      RECT 28.071 0.000 28.089 0.054 ;
    END
  END rw0_rd_out[64]
  PIN rw0_rd_out[65]
    DIRECTION OUTPUT ;
    USE SIGNAL ;
    SHAPE ABUTMENT ;
    PORT
      LAYER M3 ;
      RECT 0.207 199.887 0.225 199.941 ;
    END
  END rw0_rd_out[65]
  PIN rw0_rd_out[66]
    DIRECTION OUTPUT ;
    USE SIGNAL ;
    SHAPE ABUTMENT ;
    PORT
      LAYER M3 ;
      RECT 0.495 199.887 0.513 199.941 ;
    END
  END rw0_rd_out[66]
  PIN rw0_rd_out[67]
    DIRECTION OUTPUT ;
    USE SIGNAL ;
    SHAPE ABUTMENT ;
    PORT
      LAYER M3 ;
      RECT 0.783 199.887 0.801 199.941 ;
    END
  END rw0_rd_out[67]
  PIN rw0_rd_out[68]
    DIRECTION OUTPUT ;
    USE SIGNAL ;
    SHAPE ABUTMENT ;
    PORT
      LAYER M3 ;
      RECT 1.071 199.887 1.089 199.941 ;
    END
  END rw0_rd_out[68]
  PIN rw0_rd_out[69]
    DIRECTION OUTPUT ;
    USE SIGNAL ;
    SHAPE ABUTMENT ;
    PORT
      LAYER M3 ;
      RECT 1.359 199.887 1.377 199.941 ;
    END
  END rw0_rd_out[69]
  PIN rw0_rd_out[70]
    DIRECTION OUTPUT ;
    USE SIGNAL ;
    SHAPE ABUTMENT ;
    PORT
      LAYER M3 ;
      RECT 1.647 199.887 1.665 199.941 ;
    END
  END rw0_rd_out[70]
  PIN rw0_rd_out[71]
    DIRECTION OUTPUT ;
    USE SIGNAL ;
    SHAPE ABUTMENT ;
    PORT
      LAYER M3 ;
      RECT 1.935 199.887 1.953 199.941 ;
    END
  END rw0_rd_out[71]
  PIN rw0_rd_out[72]
    DIRECTION OUTPUT ;
    USE SIGNAL ;
    SHAPE ABUTMENT ;
    PORT
      LAYER M3 ;
      RECT 2.223 199.887 2.241 199.941 ;
    END
  END rw0_rd_out[72]
  PIN rw0_rd_out[73]
    DIRECTION OUTPUT ;
    USE SIGNAL ;
    SHAPE ABUTMENT ;
    PORT
      LAYER M3 ;
      RECT 2.511 199.887 2.529 199.941 ;
    END
  END rw0_rd_out[73]
  PIN rw0_rd_out[74]
    DIRECTION OUTPUT ;
    USE SIGNAL ;
    SHAPE ABUTMENT ;
    PORT
      LAYER M3 ;
      RECT 2.799 199.887 2.817 199.941 ;
    END
  END rw0_rd_out[74]
  PIN rw0_rd_out[75]
    DIRECTION OUTPUT ;
    USE SIGNAL ;
    SHAPE ABUTMENT ;
    PORT
      LAYER M3 ;
      RECT 3.087 199.887 3.105 199.941 ;
    END
  END rw0_rd_out[75]
  PIN rw0_rd_out[76]
    DIRECTION OUTPUT ;
    USE SIGNAL ;
    SHAPE ABUTMENT ;
    PORT
      LAYER M3 ;
      RECT 3.375 199.887 3.393 199.941 ;
    END
  END rw0_rd_out[76]
  PIN rw0_rd_out[77]
    DIRECTION OUTPUT ;
    USE SIGNAL ;
    SHAPE ABUTMENT ;
    PORT
      LAYER M3 ;
      RECT 3.663 199.887 3.681 199.941 ;
    END
  END rw0_rd_out[77]
  PIN rw0_rd_out[78]
    DIRECTION OUTPUT ;
    USE SIGNAL ;
    SHAPE ABUTMENT ;
    PORT
      LAYER M3 ;
      RECT 3.951 199.887 3.969 199.941 ;
    END
  END rw0_rd_out[78]
  PIN rw0_rd_out[79]
    DIRECTION OUTPUT ;
    USE SIGNAL ;
    SHAPE ABUTMENT ;
    PORT
      LAYER M3 ;
      RECT 4.239 199.887 4.257 199.941 ;
    END
  END rw0_rd_out[79]
  PIN rw0_rd_out[80]
    DIRECTION OUTPUT ;
    USE SIGNAL ;
    SHAPE ABUTMENT ;
    PORT
      LAYER M3 ;
      RECT 4.527 199.887 4.545 199.941 ;
    END
  END rw0_rd_out[80]
  PIN rw0_rd_out[81]
    DIRECTION OUTPUT ;
    USE SIGNAL ;
    SHAPE ABUTMENT ;
    PORT
      LAYER M3 ;
      RECT 4.815 199.887 4.833 199.941 ;
    END
  END rw0_rd_out[81]
  PIN rw0_rd_out[82]
    DIRECTION OUTPUT ;
    USE SIGNAL ;
    SHAPE ABUTMENT ;
    PORT
      LAYER M3 ;
      RECT 5.103 199.887 5.121 199.941 ;
    END
  END rw0_rd_out[82]
  PIN rw0_rd_out[83]
    DIRECTION OUTPUT ;
    USE SIGNAL ;
    SHAPE ABUTMENT ;
    PORT
      LAYER M3 ;
      RECT 5.391 199.887 5.409 199.941 ;
    END
  END rw0_rd_out[83]
  PIN rw0_rd_out[84]
    DIRECTION OUTPUT ;
    USE SIGNAL ;
    SHAPE ABUTMENT ;
    PORT
      LAYER M3 ;
      RECT 5.679 199.887 5.697 199.941 ;
    END
  END rw0_rd_out[84]
  PIN rw0_rd_out[85]
    DIRECTION OUTPUT ;
    USE SIGNAL ;
    SHAPE ABUTMENT ;
    PORT
      LAYER M3 ;
      RECT 5.967 199.887 5.985 199.941 ;
    END
  END rw0_rd_out[85]
  PIN rw0_rd_out[86]
    DIRECTION OUTPUT ;
    USE SIGNAL ;
    SHAPE ABUTMENT ;
    PORT
      LAYER M3 ;
      RECT 6.255 199.887 6.273 199.941 ;
    END
  END rw0_rd_out[86]
  PIN rw0_rd_out[87]
    DIRECTION OUTPUT ;
    USE SIGNAL ;
    SHAPE ABUTMENT ;
    PORT
      LAYER M3 ;
      RECT 6.543 199.887 6.561 199.941 ;
    END
  END rw0_rd_out[87]
  PIN rw0_rd_out[88]
    DIRECTION OUTPUT ;
    USE SIGNAL ;
    SHAPE ABUTMENT ;
    PORT
      LAYER M3 ;
      RECT 6.831 199.887 6.849 199.941 ;
    END
  END rw0_rd_out[88]
  PIN rw0_rd_out[89]
    DIRECTION OUTPUT ;
    USE SIGNAL ;
    SHAPE ABUTMENT ;
    PORT
      LAYER M3 ;
      RECT 7.119 199.887 7.137 199.941 ;
    END
  END rw0_rd_out[89]
  PIN rw0_rd_out[90]
    DIRECTION OUTPUT ;
    USE SIGNAL ;
    SHAPE ABUTMENT ;
    PORT
      LAYER M3 ;
      RECT 7.407 199.887 7.425 199.941 ;
    END
  END rw0_rd_out[90]
  PIN rw0_rd_out[91]
    DIRECTION OUTPUT ;
    USE SIGNAL ;
    SHAPE ABUTMENT ;
    PORT
      LAYER M3 ;
      RECT 7.695 199.887 7.713 199.941 ;
    END
  END rw0_rd_out[91]
  PIN rw0_rd_out[92]
    DIRECTION OUTPUT ;
    USE SIGNAL ;
    SHAPE ABUTMENT ;
    PORT
      LAYER M3 ;
      RECT 7.983 199.887 8.001 199.941 ;
    END
  END rw0_rd_out[92]
  PIN rw0_rd_out[93]
    DIRECTION OUTPUT ;
    USE SIGNAL ;
    SHAPE ABUTMENT ;
    PORT
      LAYER M3 ;
      RECT 8.271 199.887 8.289 199.941 ;
    END
  END rw0_rd_out[93]
  PIN rw0_rd_out[94]
    DIRECTION OUTPUT ;
    USE SIGNAL ;
    SHAPE ABUTMENT ;
    PORT
      LAYER M3 ;
      RECT 8.559 199.887 8.577 199.941 ;
    END
  END rw0_rd_out[94]
  PIN rw0_rd_out[95]
    DIRECTION OUTPUT ;
    USE SIGNAL ;
    SHAPE ABUTMENT ;
    PORT
      LAYER M3 ;
      RECT 8.847 199.887 8.865 199.941 ;
    END
  END rw0_rd_out[95]
  PIN rw0_rd_out[96]
    DIRECTION OUTPUT ;
    USE SIGNAL ;
    SHAPE ABUTMENT ;
    PORT
      LAYER M3 ;
      RECT 9.135 199.887 9.153 199.941 ;
    END
  END rw0_rd_out[96]
  PIN rw0_rd_out[97]
    DIRECTION OUTPUT ;
    USE SIGNAL ;
    SHAPE ABUTMENT ;
    PORT
      LAYER M3 ;
      RECT 9.423 199.887 9.441 199.941 ;
    END
  END rw0_rd_out[97]
  PIN rw0_rd_out[98]
    DIRECTION OUTPUT ;
    USE SIGNAL ;
    SHAPE ABUTMENT ;
    PORT
      LAYER M3 ;
      RECT 9.711 199.887 9.729 199.941 ;
    END
  END rw0_rd_out[98]
  PIN rw0_rd_out[99]
    DIRECTION OUTPUT ;
    USE SIGNAL ;
    SHAPE ABUTMENT ;
    PORT
      LAYER M3 ;
      RECT 9.999 199.887 10.017 199.941 ;
    END
  END rw0_rd_out[99]
  PIN rw0_rd_out[100]
    DIRECTION OUTPUT ;
    USE SIGNAL ;
    SHAPE ABUTMENT ;
    PORT
      LAYER M3 ;
      RECT 10.287 199.887 10.305 199.941 ;
    END
  END rw0_rd_out[100]
  PIN rw0_rd_out[101]
    DIRECTION OUTPUT ;
    USE SIGNAL ;
    SHAPE ABUTMENT ;
    PORT
      LAYER M3 ;
      RECT 10.575 199.887 10.593 199.941 ;
    END
  END rw0_rd_out[101]
  PIN rw0_rd_out[102]
    DIRECTION OUTPUT ;
    USE SIGNAL ;
    SHAPE ABUTMENT ;
    PORT
      LAYER M3 ;
      RECT 10.863 199.887 10.881 199.941 ;
    END
  END rw0_rd_out[102]
  PIN rw0_rd_out[103]
    DIRECTION OUTPUT ;
    USE SIGNAL ;
    SHAPE ABUTMENT ;
    PORT
      LAYER M3 ;
      RECT 11.151 199.887 11.169 199.941 ;
    END
  END rw0_rd_out[103]
  PIN rw0_rd_out[104]
    DIRECTION OUTPUT ;
    USE SIGNAL ;
    SHAPE ABUTMENT ;
    PORT
      LAYER M3 ;
      RECT 11.439 199.887 11.457 199.941 ;
    END
  END rw0_rd_out[104]
  PIN rw0_rd_out[105]
    DIRECTION OUTPUT ;
    USE SIGNAL ;
    SHAPE ABUTMENT ;
    PORT
      LAYER M3 ;
      RECT 11.727 199.887 11.745 199.941 ;
    END
  END rw0_rd_out[105]
  PIN rw0_rd_out[106]
    DIRECTION OUTPUT ;
    USE SIGNAL ;
    SHAPE ABUTMENT ;
    PORT
      LAYER M3 ;
      RECT 12.015 199.887 12.033 199.941 ;
    END
  END rw0_rd_out[106]
  PIN rw0_rd_out[107]
    DIRECTION OUTPUT ;
    USE SIGNAL ;
    SHAPE ABUTMENT ;
    PORT
      LAYER M3 ;
      RECT 12.303 199.887 12.321 199.941 ;
    END
  END rw0_rd_out[107]
  PIN rw0_rd_out[108]
    DIRECTION OUTPUT ;
    USE SIGNAL ;
    SHAPE ABUTMENT ;
    PORT
      LAYER M3 ;
      RECT 12.591 199.887 12.609 199.941 ;
    END
  END rw0_rd_out[108]
  PIN rw0_rd_out[109]
    DIRECTION OUTPUT ;
    USE SIGNAL ;
    SHAPE ABUTMENT ;
    PORT
      LAYER M3 ;
      RECT 12.879 199.887 12.897 199.941 ;
    END
  END rw0_rd_out[109]
  PIN rw0_rd_out[110]
    DIRECTION OUTPUT ;
    USE SIGNAL ;
    SHAPE ABUTMENT ;
    PORT
      LAYER M3 ;
      RECT 13.167 199.887 13.185 199.941 ;
    END
  END rw0_rd_out[110]
  PIN rw0_rd_out[111]
    DIRECTION OUTPUT ;
    USE SIGNAL ;
    SHAPE ABUTMENT ;
    PORT
      LAYER M3 ;
      RECT 13.455 199.887 13.473 199.941 ;
    END
  END rw0_rd_out[111]
  PIN rw0_rd_out[112]
    DIRECTION OUTPUT ;
    USE SIGNAL ;
    SHAPE ABUTMENT ;
    PORT
      LAYER M3 ;
      RECT 13.743 199.887 13.761 199.941 ;
    END
  END rw0_rd_out[112]
  PIN rw0_rd_out[113]
    DIRECTION OUTPUT ;
    USE SIGNAL ;
    SHAPE ABUTMENT ;
    PORT
      LAYER M3 ;
      RECT 14.031 199.887 14.049 199.941 ;
    END
  END rw0_rd_out[113]
  PIN rw0_rd_out[114]
    DIRECTION OUTPUT ;
    USE SIGNAL ;
    SHAPE ABUTMENT ;
    PORT
      LAYER M3 ;
      RECT 14.319 199.887 14.337 199.941 ;
    END
  END rw0_rd_out[114]
  PIN rw0_rd_out[115]
    DIRECTION OUTPUT ;
    USE SIGNAL ;
    SHAPE ABUTMENT ;
    PORT
      LAYER M3 ;
      RECT 14.607 199.887 14.625 199.941 ;
    END
  END rw0_rd_out[115]
  PIN rw0_rd_out[116]
    DIRECTION OUTPUT ;
    USE SIGNAL ;
    SHAPE ABUTMENT ;
    PORT
      LAYER M3 ;
      RECT 14.895 199.887 14.913 199.941 ;
    END
  END rw0_rd_out[116]
  PIN rw0_rd_out[117]
    DIRECTION OUTPUT ;
    USE SIGNAL ;
    SHAPE ABUTMENT ;
    PORT
      LAYER M3 ;
      RECT 15.183 199.887 15.201 199.941 ;
    END
  END rw0_rd_out[117]
  PIN rw0_rd_out[118]
    DIRECTION OUTPUT ;
    USE SIGNAL ;
    SHAPE ABUTMENT ;
    PORT
      LAYER M3 ;
      RECT 15.471 199.887 15.489 199.941 ;
    END
  END rw0_rd_out[118]
  PIN rw0_rd_out[119]
    DIRECTION OUTPUT ;
    USE SIGNAL ;
    SHAPE ABUTMENT ;
    PORT
      LAYER M3 ;
      RECT 15.759 199.887 15.777 199.941 ;
    END
  END rw0_rd_out[119]
  PIN rw0_rd_out[120]
    DIRECTION OUTPUT ;
    USE SIGNAL ;
    SHAPE ABUTMENT ;
    PORT
      LAYER M3 ;
      RECT 16.047 199.887 16.065 199.941 ;
    END
  END rw0_rd_out[120]
  PIN rw0_rd_out[121]
    DIRECTION OUTPUT ;
    USE SIGNAL ;
    SHAPE ABUTMENT ;
    PORT
      LAYER M3 ;
      RECT 16.335 199.887 16.353 199.941 ;
    END
  END rw0_rd_out[121]
  PIN rw0_rd_out[122]
    DIRECTION OUTPUT ;
    USE SIGNAL ;
    SHAPE ABUTMENT ;
    PORT
      LAYER M3 ;
      RECT 16.623 199.887 16.641 199.941 ;
    END
  END rw0_rd_out[122]
  PIN rw0_rd_out[123]
    DIRECTION OUTPUT ;
    USE SIGNAL ;
    SHAPE ABUTMENT ;
    PORT
      LAYER M3 ;
      RECT 16.911 199.887 16.929 199.941 ;
    END
  END rw0_rd_out[123]
  PIN rw0_rd_out[124]
    DIRECTION OUTPUT ;
    USE SIGNAL ;
    SHAPE ABUTMENT ;
    PORT
      LAYER M3 ;
      RECT 17.199 199.887 17.217 199.941 ;
    END
  END rw0_rd_out[124]
  PIN rw0_rd_out[125]
    DIRECTION OUTPUT ;
    USE SIGNAL ;
    SHAPE ABUTMENT ;
    PORT
      LAYER M3 ;
      RECT 17.487 199.887 17.505 199.941 ;
    END
  END rw0_rd_out[125]
  PIN rw0_rd_out[126]
    DIRECTION OUTPUT ;
    USE SIGNAL ;
    SHAPE ABUTMENT ;
    PORT
      LAYER M3 ;
      RECT 17.775 199.887 17.793 199.941 ;
    END
  END rw0_rd_out[126]
  PIN rw0_rd_out[127]
    DIRECTION OUTPUT ;
    USE SIGNAL ;
    SHAPE ABUTMENT ;
    PORT
      LAYER M3 ;
      RECT 18.063 199.887 18.081 199.941 ;
    END
  END rw0_rd_out[127]
  PIN rw0_rd_out[128]
    DIRECTION OUTPUT ;
    USE SIGNAL ;
    SHAPE ABUTMENT ;
    PORT
      LAYER M3 ;
      RECT 18.351 199.887 18.369 199.941 ;
    END
  END rw0_rd_out[128]
  PIN rw0_rd_out[129]
    DIRECTION OUTPUT ;
    USE SIGNAL ;
    SHAPE ABUTMENT ;
    PORT
      LAYER M3 ;
      RECT 18.639 199.887 18.657 199.941 ;
    END
  END rw0_rd_out[129]
  PIN r0_rd_out[0]
    DIRECTION OUTPUT ;
    USE SIGNAL ;
    SHAPE ABUTMENT ;
    PORT
      LAYER M3 ;
      RECT 28.287 0.000 28.305 0.054 ;
    END
  END r0_rd_out[0]
  PIN r0_rd_out[1]
    DIRECTION OUTPUT ;
    USE SIGNAL ;
    SHAPE ABUTMENT ;
    PORT
      LAYER M3 ;
      RECT 28.503 0.000 28.521 0.054 ;
    END
  END r0_rd_out[1]
  PIN r0_rd_out[2]
    DIRECTION OUTPUT ;
    USE SIGNAL ;
    SHAPE ABUTMENT ;
    PORT
      LAYER M3 ;
      RECT 28.719 0.000 28.737 0.054 ;
    END
  END r0_rd_out[2]
  PIN r0_rd_out[3]
    DIRECTION OUTPUT ;
    USE SIGNAL ;
    SHAPE ABUTMENT ;
    PORT
      LAYER M3 ;
      RECT 28.935 0.000 28.953 0.054 ;
    END
  END r0_rd_out[3]
  PIN r0_rd_out[4]
    DIRECTION OUTPUT ;
    USE SIGNAL ;
    SHAPE ABUTMENT ;
    PORT
      LAYER M3 ;
      RECT 29.151 0.000 29.169 0.054 ;
    END
  END r0_rd_out[4]
  PIN r0_rd_out[5]
    DIRECTION OUTPUT ;
    USE SIGNAL ;
    SHAPE ABUTMENT ;
    PORT
      LAYER M3 ;
      RECT 29.367 0.000 29.385 0.054 ;
    END
  END r0_rd_out[5]
  PIN r0_rd_out[6]
    DIRECTION OUTPUT ;
    USE SIGNAL ;
    SHAPE ABUTMENT ;
    PORT
      LAYER M3 ;
      RECT 29.583 0.000 29.601 0.054 ;
    END
  END r0_rd_out[6]
  PIN r0_rd_out[7]
    DIRECTION OUTPUT ;
    USE SIGNAL ;
    SHAPE ABUTMENT ;
    PORT
      LAYER M3 ;
      RECT 29.799 0.000 29.817 0.054 ;
    END
  END r0_rd_out[7]
  PIN r0_rd_out[8]
    DIRECTION OUTPUT ;
    USE SIGNAL ;
    SHAPE ABUTMENT ;
    PORT
      LAYER M3 ;
      RECT 30.015 0.000 30.033 0.054 ;
    END
  END r0_rd_out[8]
  PIN r0_rd_out[9]
    DIRECTION OUTPUT ;
    USE SIGNAL ;
    SHAPE ABUTMENT ;
    PORT
      LAYER M3 ;
      RECT 30.231 0.000 30.249 0.054 ;
    END
  END r0_rd_out[9]
  PIN r0_rd_out[10]
    DIRECTION OUTPUT ;
    USE SIGNAL ;
    SHAPE ABUTMENT ;
    PORT
      LAYER M3 ;
      RECT 30.447 0.000 30.465 0.054 ;
    END
  END r0_rd_out[10]
  PIN r0_rd_out[11]
    DIRECTION OUTPUT ;
    USE SIGNAL ;
    SHAPE ABUTMENT ;
    PORT
      LAYER M3 ;
      RECT 30.663 0.000 30.681 0.054 ;
    END
  END r0_rd_out[11]
  PIN r0_rd_out[12]
    DIRECTION OUTPUT ;
    USE SIGNAL ;
    SHAPE ABUTMENT ;
    PORT
      LAYER M3 ;
      RECT 30.879 0.000 30.897 0.054 ;
    END
  END r0_rd_out[12]
  PIN r0_rd_out[13]
    DIRECTION OUTPUT ;
    USE SIGNAL ;
    SHAPE ABUTMENT ;
    PORT
      LAYER M3 ;
      RECT 31.095 0.000 31.113 0.054 ;
    END
  END r0_rd_out[13]
  PIN r0_rd_out[14]
    DIRECTION OUTPUT ;
    USE SIGNAL ;
    SHAPE ABUTMENT ;
    PORT
      LAYER M3 ;
      RECT 31.311 0.000 31.329 0.054 ;
    END
  END r0_rd_out[14]
  PIN r0_rd_out[15]
    DIRECTION OUTPUT ;
    USE SIGNAL ;
    SHAPE ABUTMENT ;
    PORT
      LAYER M3 ;
      RECT 31.527 0.000 31.545 0.054 ;
    END
  END r0_rd_out[15]
  PIN r0_rd_out[16]
    DIRECTION OUTPUT ;
    USE SIGNAL ;
    SHAPE ABUTMENT ;
    PORT
      LAYER M3 ;
      RECT 31.743 0.000 31.761 0.054 ;
    END
  END r0_rd_out[16]
  PIN r0_rd_out[17]
    DIRECTION OUTPUT ;
    USE SIGNAL ;
    SHAPE ABUTMENT ;
    PORT
      LAYER M3 ;
      RECT 31.959 0.000 31.977 0.054 ;
    END
  END r0_rd_out[17]
  PIN r0_rd_out[18]
    DIRECTION OUTPUT ;
    USE SIGNAL ;
    SHAPE ABUTMENT ;
    PORT
      LAYER M3 ;
      RECT 32.175 0.000 32.193 0.054 ;
    END
  END r0_rd_out[18]
  PIN r0_rd_out[19]
    DIRECTION OUTPUT ;
    USE SIGNAL ;
    SHAPE ABUTMENT ;
    PORT
      LAYER M3 ;
      RECT 32.391 0.000 32.409 0.054 ;
    END
  END r0_rd_out[19]
  PIN r0_rd_out[20]
    DIRECTION OUTPUT ;
    USE SIGNAL ;
    SHAPE ABUTMENT ;
    PORT
      LAYER M3 ;
      RECT 32.607 0.000 32.625 0.054 ;
    END
  END r0_rd_out[20]
  PIN r0_rd_out[21]
    DIRECTION OUTPUT ;
    USE SIGNAL ;
    SHAPE ABUTMENT ;
    PORT
      LAYER M3 ;
      RECT 32.823 0.000 32.841 0.054 ;
    END
  END r0_rd_out[21]
  PIN r0_rd_out[22]
    DIRECTION OUTPUT ;
    USE SIGNAL ;
    SHAPE ABUTMENT ;
    PORT
      LAYER M3 ;
      RECT 33.039 0.000 33.057 0.054 ;
    END
  END r0_rd_out[22]
  PIN r0_rd_out[23]
    DIRECTION OUTPUT ;
    USE SIGNAL ;
    SHAPE ABUTMENT ;
    PORT
      LAYER M3 ;
      RECT 33.255 0.000 33.273 0.054 ;
    END
  END r0_rd_out[23]
  PIN r0_rd_out[24]
    DIRECTION OUTPUT ;
    USE SIGNAL ;
    SHAPE ABUTMENT ;
    PORT
      LAYER M3 ;
      RECT 33.471 0.000 33.489 0.054 ;
    END
  END r0_rd_out[24]
  PIN r0_rd_out[25]
    DIRECTION OUTPUT ;
    USE SIGNAL ;
    SHAPE ABUTMENT ;
    PORT
      LAYER M3 ;
      RECT 33.687 0.000 33.705 0.054 ;
    END
  END r0_rd_out[25]
  PIN r0_rd_out[26]
    DIRECTION OUTPUT ;
    USE SIGNAL ;
    SHAPE ABUTMENT ;
    PORT
      LAYER M3 ;
      RECT 33.903 0.000 33.921 0.054 ;
    END
  END r0_rd_out[26]
  PIN r0_rd_out[27]
    DIRECTION OUTPUT ;
    USE SIGNAL ;
    SHAPE ABUTMENT ;
    PORT
      LAYER M3 ;
      RECT 34.119 0.000 34.137 0.054 ;
    END
  END r0_rd_out[27]
  PIN r0_rd_out[28]
    DIRECTION OUTPUT ;
    USE SIGNAL ;
    SHAPE ABUTMENT ;
    PORT
      LAYER M3 ;
      RECT 34.335 0.000 34.353 0.054 ;
    END
  END r0_rd_out[28]
  PIN r0_rd_out[29]
    DIRECTION OUTPUT ;
    USE SIGNAL ;
    SHAPE ABUTMENT ;
    PORT
      LAYER M3 ;
      RECT 34.551 0.000 34.569 0.054 ;
    END
  END r0_rd_out[29]
  PIN r0_rd_out[30]
    DIRECTION OUTPUT ;
    USE SIGNAL ;
    SHAPE ABUTMENT ;
    PORT
      LAYER M3 ;
      RECT 34.767 0.000 34.785 0.054 ;
    END
  END r0_rd_out[30]
  PIN r0_rd_out[31]
    DIRECTION OUTPUT ;
    USE SIGNAL ;
    SHAPE ABUTMENT ;
    PORT
      LAYER M3 ;
      RECT 34.983 0.000 35.001 0.054 ;
    END
  END r0_rd_out[31]
  PIN r0_rd_out[32]
    DIRECTION OUTPUT ;
    USE SIGNAL ;
    SHAPE ABUTMENT ;
    PORT
      LAYER M3 ;
      RECT 35.199 0.000 35.217 0.054 ;
    END
  END r0_rd_out[32]
  PIN r0_rd_out[33]
    DIRECTION OUTPUT ;
    USE SIGNAL ;
    SHAPE ABUTMENT ;
    PORT
      LAYER M3 ;
      RECT 35.415 0.000 35.433 0.054 ;
    END
  END r0_rd_out[33]
  PIN r0_rd_out[34]
    DIRECTION OUTPUT ;
    USE SIGNAL ;
    SHAPE ABUTMENT ;
    PORT
      LAYER M3 ;
      RECT 35.631 0.000 35.649 0.054 ;
    END
  END r0_rd_out[34]
  PIN r0_rd_out[35]
    DIRECTION OUTPUT ;
    USE SIGNAL ;
    SHAPE ABUTMENT ;
    PORT
      LAYER M3 ;
      RECT 35.847 0.000 35.865 0.054 ;
    END
  END r0_rd_out[35]
  PIN r0_rd_out[36]
    DIRECTION OUTPUT ;
    USE SIGNAL ;
    SHAPE ABUTMENT ;
    PORT
      LAYER M3 ;
      RECT 36.063 0.000 36.081 0.054 ;
    END
  END r0_rd_out[36]
  PIN r0_rd_out[37]
    DIRECTION OUTPUT ;
    USE SIGNAL ;
    SHAPE ABUTMENT ;
    PORT
      LAYER M3 ;
      RECT 36.279 0.000 36.297 0.054 ;
    END
  END r0_rd_out[37]
  PIN r0_rd_out[38]
    DIRECTION OUTPUT ;
    USE SIGNAL ;
    SHAPE ABUTMENT ;
    PORT
      LAYER M3 ;
      RECT 36.495 0.000 36.513 0.054 ;
    END
  END r0_rd_out[38]
  PIN r0_rd_out[39]
    DIRECTION OUTPUT ;
    USE SIGNAL ;
    SHAPE ABUTMENT ;
    PORT
      LAYER M3 ;
      RECT 36.711 0.000 36.729 0.054 ;
    END
  END r0_rd_out[39]
  PIN r0_rd_out[40]
    DIRECTION OUTPUT ;
    USE SIGNAL ;
    SHAPE ABUTMENT ;
    PORT
      LAYER M3 ;
      RECT 36.927 0.000 36.945 0.054 ;
    END
  END r0_rd_out[40]
  PIN r0_rd_out[41]
    DIRECTION OUTPUT ;
    USE SIGNAL ;
    SHAPE ABUTMENT ;
    PORT
      LAYER M3 ;
      RECT 37.143 0.000 37.161 0.054 ;
    END
  END r0_rd_out[41]
  PIN r0_rd_out[42]
    DIRECTION OUTPUT ;
    USE SIGNAL ;
    SHAPE ABUTMENT ;
    PORT
      LAYER M3 ;
      RECT 37.359 0.000 37.377 0.054 ;
    END
  END r0_rd_out[42]
  PIN r0_rd_out[43]
    DIRECTION OUTPUT ;
    USE SIGNAL ;
    SHAPE ABUTMENT ;
    PORT
      LAYER M3 ;
      RECT 37.575 0.000 37.593 0.054 ;
    END
  END r0_rd_out[43]
  PIN r0_rd_out[44]
    DIRECTION OUTPUT ;
    USE SIGNAL ;
    SHAPE ABUTMENT ;
    PORT
      LAYER M3 ;
      RECT 37.791 0.000 37.809 0.054 ;
    END
  END r0_rd_out[44]
  PIN r0_rd_out[45]
    DIRECTION OUTPUT ;
    USE SIGNAL ;
    SHAPE ABUTMENT ;
    PORT
      LAYER M3 ;
      RECT 38.007 0.000 38.025 0.054 ;
    END
  END r0_rd_out[45]
  PIN r0_rd_out[46]
    DIRECTION OUTPUT ;
    USE SIGNAL ;
    SHAPE ABUTMENT ;
    PORT
      LAYER M3 ;
      RECT 38.223 0.000 38.241 0.054 ;
    END
  END r0_rd_out[46]
  PIN r0_rd_out[47]
    DIRECTION OUTPUT ;
    USE SIGNAL ;
    SHAPE ABUTMENT ;
    PORT
      LAYER M3 ;
      RECT 38.439 0.000 38.457 0.054 ;
    END
  END r0_rd_out[47]
  PIN r0_rd_out[48]
    DIRECTION OUTPUT ;
    USE SIGNAL ;
    SHAPE ABUTMENT ;
    PORT
      LAYER M3 ;
      RECT 38.655 0.000 38.673 0.054 ;
    END
  END r0_rd_out[48]
  PIN r0_rd_out[49]
    DIRECTION OUTPUT ;
    USE SIGNAL ;
    SHAPE ABUTMENT ;
    PORT
      LAYER M3 ;
      RECT 38.871 0.000 38.889 0.054 ;
    END
  END r0_rd_out[49]
  PIN r0_rd_out[50]
    DIRECTION OUTPUT ;
    USE SIGNAL ;
    SHAPE ABUTMENT ;
    PORT
      LAYER M3 ;
      RECT 39.087 0.000 39.105 0.054 ;
    END
  END r0_rd_out[50]
  PIN r0_rd_out[51]
    DIRECTION OUTPUT ;
    USE SIGNAL ;
    SHAPE ABUTMENT ;
    PORT
      LAYER M3 ;
      RECT 39.303 0.000 39.321 0.054 ;
    END
  END r0_rd_out[51]
  PIN r0_rd_out[52]
    DIRECTION OUTPUT ;
    USE SIGNAL ;
    SHAPE ABUTMENT ;
    PORT
      LAYER M3 ;
      RECT 39.519 0.000 39.537 0.054 ;
    END
  END r0_rd_out[52]
  PIN r0_rd_out[53]
    DIRECTION OUTPUT ;
    USE SIGNAL ;
    SHAPE ABUTMENT ;
    PORT
      LAYER M3 ;
      RECT 39.735 0.000 39.753 0.054 ;
    END
  END r0_rd_out[53]
  PIN r0_rd_out[54]
    DIRECTION OUTPUT ;
    USE SIGNAL ;
    SHAPE ABUTMENT ;
    PORT
      LAYER M3 ;
      RECT 39.951 0.000 39.969 0.054 ;
    END
  END r0_rd_out[54]
  PIN r0_rd_out[55]
    DIRECTION OUTPUT ;
    USE SIGNAL ;
    SHAPE ABUTMENT ;
    PORT
      LAYER M3 ;
      RECT 40.167 0.000 40.185 0.054 ;
    END
  END r0_rd_out[55]
  PIN r0_rd_out[56]
    DIRECTION OUTPUT ;
    USE SIGNAL ;
    SHAPE ABUTMENT ;
    PORT
      LAYER M3 ;
      RECT 40.383 0.000 40.401 0.054 ;
    END
  END r0_rd_out[56]
  PIN r0_rd_out[57]
    DIRECTION OUTPUT ;
    USE SIGNAL ;
    SHAPE ABUTMENT ;
    PORT
      LAYER M3 ;
      RECT 40.599 0.000 40.617 0.054 ;
    END
  END r0_rd_out[57]
  PIN r0_rd_out[58]
    DIRECTION OUTPUT ;
    USE SIGNAL ;
    SHAPE ABUTMENT ;
    PORT
      LAYER M3 ;
      RECT 40.815 0.000 40.833 0.054 ;
    END
  END r0_rd_out[58]
  PIN r0_rd_out[59]
    DIRECTION OUTPUT ;
    USE SIGNAL ;
    SHAPE ABUTMENT ;
    PORT
      LAYER M3 ;
      RECT 41.031 0.000 41.049 0.054 ;
    END
  END r0_rd_out[59]
  PIN r0_rd_out[60]
    DIRECTION OUTPUT ;
    USE SIGNAL ;
    SHAPE ABUTMENT ;
    PORT
      LAYER M3 ;
      RECT 41.247 0.000 41.265 0.054 ;
    END
  END r0_rd_out[60]
  PIN r0_rd_out[61]
    DIRECTION OUTPUT ;
    USE SIGNAL ;
    SHAPE ABUTMENT ;
    PORT
      LAYER M3 ;
      RECT 41.463 0.000 41.481 0.054 ;
    END
  END r0_rd_out[61]
  PIN r0_rd_out[62]
    DIRECTION OUTPUT ;
    USE SIGNAL ;
    SHAPE ABUTMENT ;
    PORT
      LAYER M3 ;
      RECT 41.679 0.000 41.697 0.054 ;
    END
  END r0_rd_out[62]
  PIN r0_rd_out[63]
    DIRECTION OUTPUT ;
    USE SIGNAL ;
    SHAPE ABUTMENT ;
    PORT
      LAYER M3 ;
      RECT 41.895 0.000 41.913 0.054 ;
    END
  END r0_rd_out[63]
  PIN r0_rd_out[64]
    DIRECTION OUTPUT ;
    USE SIGNAL ;
    SHAPE ABUTMENT ;
    PORT
      LAYER M3 ;
      RECT 42.111 0.000 42.129 0.054 ;
    END
  END r0_rd_out[64]
  PIN r0_rd_out[65]
    DIRECTION OUTPUT ;
    USE SIGNAL ;
    SHAPE ABUTMENT ;
    PORT
      LAYER M3 ;
      RECT 18.927 199.887 18.945 199.941 ;
    END
  END r0_rd_out[65]
  PIN r0_rd_out[66]
    DIRECTION OUTPUT ;
    USE SIGNAL ;
    SHAPE ABUTMENT ;
    PORT
      LAYER M3 ;
      RECT 19.215 199.887 19.233 199.941 ;
    END
  END r0_rd_out[66]
  PIN r0_rd_out[67]
    DIRECTION OUTPUT ;
    USE SIGNAL ;
    SHAPE ABUTMENT ;
    PORT
      LAYER M3 ;
      RECT 19.503 199.887 19.521 199.941 ;
    END
  END r0_rd_out[67]
  PIN r0_rd_out[68]
    DIRECTION OUTPUT ;
    USE SIGNAL ;
    SHAPE ABUTMENT ;
    PORT
      LAYER M3 ;
      RECT 19.791 199.887 19.809 199.941 ;
    END
  END r0_rd_out[68]
  PIN r0_rd_out[69]
    DIRECTION OUTPUT ;
    USE SIGNAL ;
    SHAPE ABUTMENT ;
    PORT
      LAYER M3 ;
      RECT 20.079 199.887 20.097 199.941 ;
    END
  END r0_rd_out[69]
  PIN r0_rd_out[70]
    DIRECTION OUTPUT ;
    USE SIGNAL ;
    SHAPE ABUTMENT ;
    PORT
      LAYER M3 ;
      RECT 20.367 199.887 20.385 199.941 ;
    END
  END r0_rd_out[70]
  PIN r0_rd_out[71]
    DIRECTION OUTPUT ;
    USE SIGNAL ;
    SHAPE ABUTMENT ;
    PORT
      LAYER M3 ;
      RECT 20.655 199.887 20.673 199.941 ;
    END
  END r0_rd_out[71]
  PIN r0_rd_out[72]
    DIRECTION OUTPUT ;
    USE SIGNAL ;
    SHAPE ABUTMENT ;
    PORT
      LAYER M3 ;
      RECT 20.943 199.887 20.961 199.941 ;
    END
  END r0_rd_out[72]
  PIN r0_rd_out[73]
    DIRECTION OUTPUT ;
    USE SIGNAL ;
    SHAPE ABUTMENT ;
    PORT
      LAYER M3 ;
      RECT 21.231 199.887 21.249 199.941 ;
    END
  END r0_rd_out[73]
  PIN r0_rd_out[74]
    DIRECTION OUTPUT ;
    USE SIGNAL ;
    SHAPE ABUTMENT ;
    PORT
      LAYER M3 ;
      RECT 21.519 199.887 21.537 199.941 ;
    END
  END r0_rd_out[74]
  PIN r0_rd_out[75]
    DIRECTION OUTPUT ;
    USE SIGNAL ;
    SHAPE ABUTMENT ;
    PORT
      LAYER M3 ;
      RECT 21.807 199.887 21.825 199.941 ;
    END
  END r0_rd_out[75]
  PIN r0_rd_out[76]
    DIRECTION OUTPUT ;
    USE SIGNAL ;
    SHAPE ABUTMENT ;
    PORT
      LAYER M3 ;
      RECT 22.095 199.887 22.113 199.941 ;
    END
  END r0_rd_out[76]
  PIN r0_rd_out[77]
    DIRECTION OUTPUT ;
    USE SIGNAL ;
    SHAPE ABUTMENT ;
    PORT
      LAYER M3 ;
      RECT 22.383 199.887 22.401 199.941 ;
    END
  END r0_rd_out[77]
  PIN r0_rd_out[78]
    DIRECTION OUTPUT ;
    USE SIGNAL ;
    SHAPE ABUTMENT ;
    PORT
      LAYER M3 ;
      RECT 22.671 199.887 22.689 199.941 ;
    END
  END r0_rd_out[78]
  PIN r0_rd_out[79]
    DIRECTION OUTPUT ;
    USE SIGNAL ;
    SHAPE ABUTMENT ;
    PORT
      LAYER M3 ;
      RECT 22.959 199.887 22.977 199.941 ;
    END
  END r0_rd_out[79]
  PIN r0_rd_out[80]
    DIRECTION OUTPUT ;
    USE SIGNAL ;
    SHAPE ABUTMENT ;
    PORT
      LAYER M3 ;
      RECT 23.247 199.887 23.265 199.941 ;
    END
  END r0_rd_out[80]
  PIN r0_rd_out[81]
    DIRECTION OUTPUT ;
    USE SIGNAL ;
    SHAPE ABUTMENT ;
    PORT
      LAYER M3 ;
      RECT 23.535 199.887 23.553 199.941 ;
    END
  END r0_rd_out[81]
  PIN r0_rd_out[82]
    DIRECTION OUTPUT ;
    USE SIGNAL ;
    SHAPE ABUTMENT ;
    PORT
      LAYER M3 ;
      RECT 23.823 199.887 23.841 199.941 ;
    END
  END r0_rd_out[82]
  PIN r0_rd_out[83]
    DIRECTION OUTPUT ;
    USE SIGNAL ;
    SHAPE ABUTMENT ;
    PORT
      LAYER M3 ;
      RECT 24.111 199.887 24.129 199.941 ;
    END
  END r0_rd_out[83]
  PIN r0_rd_out[84]
    DIRECTION OUTPUT ;
    USE SIGNAL ;
    SHAPE ABUTMENT ;
    PORT
      LAYER M3 ;
      RECT 24.399 199.887 24.417 199.941 ;
    END
  END r0_rd_out[84]
  PIN r0_rd_out[85]
    DIRECTION OUTPUT ;
    USE SIGNAL ;
    SHAPE ABUTMENT ;
    PORT
      LAYER M3 ;
      RECT 24.687 199.887 24.705 199.941 ;
    END
  END r0_rd_out[85]
  PIN r0_rd_out[86]
    DIRECTION OUTPUT ;
    USE SIGNAL ;
    SHAPE ABUTMENT ;
    PORT
      LAYER M3 ;
      RECT 24.975 199.887 24.993 199.941 ;
    END
  END r0_rd_out[86]
  PIN r0_rd_out[87]
    DIRECTION OUTPUT ;
    USE SIGNAL ;
    SHAPE ABUTMENT ;
    PORT
      LAYER M3 ;
      RECT 25.263 199.887 25.281 199.941 ;
    END
  END r0_rd_out[87]
  PIN r0_rd_out[88]
    DIRECTION OUTPUT ;
    USE SIGNAL ;
    SHAPE ABUTMENT ;
    PORT
      LAYER M3 ;
      RECT 25.551 199.887 25.569 199.941 ;
    END
  END r0_rd_out[88]
  PIN r0_rd_out[89]
    DIRECTION OUTPUT ;
    USE SIGNAL ;
    SHAPE ABUTMENT ;
    PORT
      LAYER M3 ;
      RECT 25.839 199.887 25.857 199.941 ;
    END
  END r0_rd_out[89]
  PIN r0_rd_out[90]
    DIRECTION OUTPUT ;
    USE SIGNAL ;
    SHAPE ABUTMENT ;
    PORT
      LAYER M3 ;
      RECT 26.127 199.887 26.145 199.941 ;
    END
  END r0_rd_out[90]
  PIN r0_rd_out[91]
    DIRECTION OUTPUT ;
    USE SIGNAL ;
    SHAPE ABUTMENT ;
    PORT
      LAYER M3 ;
      RECT 26.415 199.887 26.433 199.941 ;
    END
  END r0_rd_out[91]
  PIN r0_rd_out[92]
    DIRECTION OUTPUT ;
    USE SIGNAL ;
    SHAPE ABUTMENT ;
    PORT
      LAYER M3 ;
      RECT 26.703 199.887 26.721 199.941 ;
    END
  END r0_rd_out[92]
  PIN r0_rd_out[93]
    DIRECTION OUTPUT ;
    USE SIGNAL ;
    SHAPE ABUTMENT ;
    PORT
      LAYER M3 ;
      RECT 26.991 199.887 27.009 199.941 ;
    END
  END r0_rd_out[93]
  PIN r0_rd_out[94]
    DIRECTION OUTPUT ;
    USE SIGNAL ;
    SHAPE ABUTMENT ;
    PORT
      LAYER M3 ;
      RECT 27.279 199.887 27.297 199.941 ;
    END
  END r0_rd_out[94]
  PIN r0_rd_out[95]
    DIRECTION OUTPUT ;
    USE SIGNAL ;
    SHAPE ABUTMENT ;
    PORT
      LAYER M3 ;
      RECT 27.567 199.887 27.585 199.941 ;
    END
  END r0_rd_out[95]
  PIN r0_rd_out[96]
    DIRECTION OUTPUT ;
    USE SIGNAL ;
    SHAPE ABUTMENT ;
    PORT
      LAYER M3 ;
      RECT 27.855 199.887 27.873 199.941 ;
    END
  END r0_rd_out[96]
  PIN r0_rd_out[97]
    DIRECTION OUTPUT ;
    USE SIGNAL ;
    SHAPE ABUTMENT ;
    PORT
      LAYER M3 ;
      RECT 28.143 199.887 28.161 199.941 ;
    END
  END r0_rd_out[97]
  PIN r0_rd_out[98]
    DIRECTION OUTPUT ;
    USE SIGNAL ;
    SHAPE ABUTMENT ;
    PORT
      LAYER M3 ;
      RECT 28.431 199.887 28.449 199.941 ;
    END
  END r0_rd_out[98]
  PIN r0_rd_out[99]
    DIRECTION OUTPUT ;
    USE SIGNAL ;
    SHAPE ABUTMENT ;
    PORT
      LAYER M3 ;
      RECT 28.719 199.887 28.737 199.941 ;
    END
  END r0_rd_out[99]
  PIN r0_rd_out[100]
    DIRECTION OUTPUT ;
    USE SIGNAL ;
    SHAPE ABUTMENT ;
    PORT
      LAYER M3 ;
      RECT 29.007 199.887 29.025 199.941 ;
    END
  END r0_rd_out[100]
  PIN r0_rd_out[101]
    DIRECTION OUTPUT ;
    USE SIGNAL ;
    SHAPE ABUTMENT ;
    PORT
      LAYER M3 ;
      RECT 29.295 199.887 29.313 199.941 ;
    END
  END r0_rd_out[101]
  PIN r0_rd_out[102]
    DIRECTION OUTPUT ;
    USE SIGNAL ;
    SHAPE ABUTMENT ;
    PORT
      LAYER M3 ;
      RECT 29.583 199.887 29.601 199.941 ;
    END
  END r0_rd_out[102]
  PIN r0_rd_out[103]
    DIRECTION OUTPUT ;
    USE SIGNAL ;
    SHAPE ABUTMENT ;
    PORT
      LAYER M3 ;
      RECT 29.871 199.887 29.889 199.941 ;
    END
  END r0_rd_out[103]
  PIN r0_rd_out[104]
    DIRECTION OUTPUT ;
    USE SIGNAL ;
    SHAPE ABUTMENT ;
    PORT
      LAYER M3 ;
      RECT 30.159 199.887 30.177 199.941 ;
    END
  END r0_rd_out[104]
  PIN r0_rd_out[105]
    DIRECTION OUTPUT ;
    USE SIGNAL ;
    SHAPE ABUTMENT ;
    PORT
      LAYER M3 ;
      RECT 30.447 199.887 30.465 199.941 ;
    END
  END r0_rd_out[105]
  PIN r0_rd_out[106]
    DIRECTION OUTPUT ;
    USE SIGNAL ;
    SHAPE ABUTMENT ;
    PORT
      LAYER M3 ;
      RECT 30.735 199.887 30.753 199.941 ;
    END
  END r0_rd_out[106]
  PIN r0_rd_out[107]
    DIRECTION OUTPUT ;
    USE SIGNAL ;
    SHAPE ABUTMENT ;
    PORT
      LAYER M3 ;
      RECT 31.023 199.887 31.041 199.941 ;
    END
  END r0_rd_out[107]
  PIN r0_rd_out[108]
    DIRECTION OUTPUT ;
    USE SIGNAL ;
    SHAPE ABUTMENT ;
    PORT
      LAYER M3 ;
      RECT 31.311 199.887 31.329 199.941 ;
    END
  END r0_rd_out[108]
  PIN r0_rd_out[109]
    DIRECTION OUTPUT ;
    USE SIGNAL ;
    SHAPE ABUTMENT ;
    PORT
      LAYER M3 ;
      RECT 31.599 199.887 31.617 199.941 ;
    END
  END r0_rd_out[109]
  PIN r0_rd_out[110]
    DIRECTION OUTPUT ;
    USE SIGNAL ;
    SHAPE ABUTMENT ;
    PORT
      LAYER M3 ;
      RECT 31.887 199.887 31.905 199.941 ;
    END
  END r0_rd_out[110]
  PIN r0_rd_out[111]
    DIRECTION OUTPUT ;
    USE SIGNAL ;
    SHAPE ABUTMENT ;
    PORT
      LAYER M3 ;
      RECT 32.175 199.887 32.193 199.941 ;
    END
  END r0_rd_out[111]
  PIN r0_rd_out[112]
    DIRECTION OUTPUT ;
    USE SIGNAL ;
    SHAPE ABUTMENT ;
    PORT
      LAYER M3 ;
      RECT 32.463 199.887 32.481 199.941 ;
    END
  END r0_rd_out[112]
  PIN r0_rd_out[113]
    DIRECTION OUTPUT ;
    USE SIGNAL ;
    SHAPE ABUTMENT ;
    PORT
      LAYER M3 ;
      RECT 32.751 199.887 32.769 199.941 ;
    END
  END r0_rd_out[113]
  PIN r0_rd_out[114]
    DIRECTION OUTPUT ;
    USE SIGNAL ;
    SHAPE ABUTMENT ;
    PORT
      LAYER M3 ;
      RECT 33.039 199.887 33.057 199.941 ;
    END
  END r0_rd_out[114]
  PIN r0_rd_out[115]
    DIRECTION OUTPUT ;
    USE SIGNAL ;
    SHAPE ABUTMENT ;
    PORT
      LAYER M3 ;
      RECT 33.327 199.887 33.345 199.941 ;
    END
  END r0_rd_out[115]
  PIN r0_rd_out[116]
    DIRECTION OUTPUT ;
    USE SIGNAL ;
    SHAPE ABUTMENT ;
    PORT
      LAYER M3 ;
      RECT 33.615 199.887 33.633 199.941 ;
    END
  END r0_rd_out[116]
  PIN r0_rd_out[117]
    DIRECTION OUTPUT ;
    USE SIGNAL ;
    SHAPE ABUTMENT ;
    PORT
      LAYER M3 ;
      RECT 33.903 199.887 33.921 199.941 ;
    END
  END r0_rd_out[117]
  PIN r0_rd_out[118]
    DIRECTION OUTPUT ;
    USE SIGNAL ;
    SHAPE ABUTMENT ;
    PORT
      LAYER M3 ;
      RECT 34.191 199.887 34.209 199.941 ;
    END
  END r0_rd_out[118]
  PIN r0_rd_out[119]
    DIRECTION OUTPUT ;
    USE SIGNAL ;
    SHAPE ABUTMENT ;
    PORT
      LAYER M3 ;
      RECT 34.479 199.887 34.497 199.941 ;
    END
  END r0_rd_out[119]
  PIN r0_rd_out[120]
    DIRECTION OUTPUT ;
    USE SIGNAL ;
    SHAPE ABUTMENT ;
    PORT
      LAYER M3 ;
      RECT 34.767 199.887 34.785 199.941 ;
    END
  END r0_rd_out[120]
  PIN r0_rd_out[121]
    DIRECTION OUTPUT ;
    USE SIGNAL ;
    SHAPE ABUTMENT ;
    PORT
      LAYER M3 ;
      RECT 35.055 199.887 35.073 199.941 ;
    END
  END r0_rd_out[121]
  PIN r0_rd_out[122]
    DIRECTION OUTPUT ;
    USE SIGNAL ;
    SHAPE ABUTMENT ;
    PORT
      LAYER M3 ;
      RECT 35.343 199.887 35.361 199.941 ;
    END
  END r0_rd_out[122]
  PIN r0_rd_out[123]
    DIRECTION OUTPUT ;
    USE SIGNAL ;
    SHAPE ABUTMENT ;
    PORT
      LAYER M3 ;
      RECT 35.631 199.887 35.649 199.941 ;
    END
  END r0_rd_out[123]
  PIN r0_rd_out[124]
    DIRECTION OUTPUT ;
    USE SIGNAL ;
    SHAPE ABUTMENT ;
    PORT
      LAYER M3 ;
      RECT 35.919 199.887 35.937 199.941 ;
    END
  END r0_rd_out[124]
  PIN r0_rd_out[125]
    DIRECTION OUTPUT ;
    USE SIGNAL ;
    SHAPE ABUTMENT ;
    PORT
      LAYER M3 ;
      RECT 36.207 199.887 36.225 199.941 ;
    END
  END r0_rd_out[125]
  PIN r0_rd_out[126]
    DIRECTION OUTPUT ;
    USE SIGNAL ;
    SHAPE ABUTMENT ;
    PORT
      LAYER M3 ;
      RECT 36.495 199.887 36.513 199.941 ;
    END
  END r0_rd_out[126]
  PIN r0_rd_out[127]
    DIRECTION OUTPUT ;
    USE SIGNAL ;
    SHAPE ABUTMENT ;
    PORT
      LAYER M3 ;
      RECT 36.783 199.887 36.801 199.941 ;
    END
  END r0_rd_out[127]
  PIN r0_rd_out[128]
    DIRECTION OUTPUT ;
    USE SIGNAL ;
    SHAPE ABUTMENT ;
    PORT
      LAYER M3 ;
      RECT 37.071 199.887 37.089 199.941 ;
    END
  END r0_rd_out[128]
  PIN r0_rd_out[129]
    DIRECTION OUTPUT ;
    USE SIGNAL ;
    SHAPE ABUTMENT ;
    PORT
      LAYER M3 ;
      RECT 37.359 199.887 37.377 199.941 ;
    END
  END r0_rd_out[129]
  PIN rw0_addr_in[0]
    DIRECTION INPUT ;
    USE SIGNAL ;
    SHAPE ABUTMENT ;
    PORT
      LAYER M4 ;
      RECT 0.000 152.340 0.072 152.364 ;
    END
  END rw0_addr_in[0]
  PIN rw0_addr_in[1]
    DIRECTION INPUT ;
    USE SIGNAL ;
    SHAPE ABUTMENT ;
    PORT
      LAYER M4 ;
      RECT 0.000 156.948 0.072 156.972 ;
    END
  END rw0_addr_in[1]
  PIN rw0_addr_in[2]
    DIRECTION INPUT ;
    USE SIGNAL ;
    SHAPE ABUTMENT ;
    PORT
      LAYER M4 ;
      RECT 0.000 161.556 0.072 161.580 ;
    END
  END rw0_addr_in[2]
  PIN rw0_addr_in[3]
    DIRECTION INPUT ;
    USE SIGNAL ;
    SHAPE ABUTMENT ;
    PORT
      LAYER M4 ;
      RECT 0.000 166.164 0.072 166.188 ;
    END
  END rw0_addr_in[3]
  PIN rw0_addr_in[4]
    DIRECTION INPUT ;
    USE SIGNAL ;
    SHAPE ABUTMENT ;
    PORT
      LAYER M4 ;
      RECT 0.000 170.772 0.072 170.796 ;
    END
  END rw0_addr_in[4]
  PIN rw0_addr_in[5]
    DIRECTION INPUT ;
    USE SIGNAL ;
    SHAPE ABUTMENT ;
    PORT
      LAYER M4 ;
      RECT 42.891 147.732 42.963 147.756 ;
    END
  END rw0_addr_in[5]
  PIN rw0_addr_in[6]
    DIRECTION INPUT ;
    USE SIGNAL ;
    SHAPE ABUTMENT ;
    PORT
      LAYER M4 ;
      RECT 42.891 152.340 42.963 152.364 ;
    END
  END rw0_addr_in[6]
  PIN rw0_addr_in[7]
    DIRECTION INPUT ;
    USE SIGNAL ;
    SHAPE ABUTMENT ;
    PORT
      LAYER M4 ;
      RECT 42.891 156.948 42.963 156.972 ;
    END
  END rw0_addr_in[7]
  PIN rw0_addr_in[8]
    DIRECTION INPUT ;
    USE SIGNAL ;
    SHAPE ABUTMENT ;
    PORT
      LAYER M4 ;
      RECT 42.891 161.556 42.963 161.580 ;
    END
  END rw0_addr_in[8]
  PIN rw0_addr_in[9]
    DIRECTION INPUT ;
    USE SIGNAL ;
    SHAPE ABUTMENT ;
    PORT
      LAYER M4 ;
      RECT 42.891 166.164 42.963 166.188 ;
    END
  END rw0_addr_in[9]
  PIN r0_addr_in[0]
    DIRECTION INPUT ;
    USE SIGNAL ;
    SHAPE ABUTMENT ;
    PORT
      LAYER M4 ;
      RECT 0.000 175.380 0.072 175.404 ;
    END
  END r0_addr_in[0]
  PIN r0_addr_in[1]
    DIRECTION INPUT ;
    USE SIGNAL ;
    SHAPE ABUTMENT ;
    PORT
      LAYER M4 ;
      RECT 0.000 179.988 0.072 180.012 ;
    END
  END r0_addr_in[1]
  PIN r0_addr_in[2]
    DIRECTION INPUT ;
    USE SIGNAL ;
    SHAPE ABUTMENT ;
    PORT
      LAYER M4 ;
      RECT 0.000 184.596 0.072 184.620 ;
    END
  END r0_addr_in[2]
  PIN r0_addr_in[3]
    DIRECTION INPUT ;
    USE SIGNAL ;
    SHAPE ABUTMENT ;
    PORT
      LAYER M4 ;
      RECT 0.000 189.204 0.072 189.228 ;
    END
  END r0_addr_in[3]
  PIN r0_addr_in[4]
    DIRECTION INPUT ;
    USE SIGNAL ;
    SHAPE ABUTMENT ;
    PORT
      LAYER M4 ;
      RECT 0.000 193.812 0.072 193.836 ;
    END
  END r0_addr_in[4]
  PIN r0_addr_in[5]
    DIRECTION INPUT ;
    USE SIGNAL ;
    SHAPE ABUTMENT ;
    PORT
      LAYER M4 ;
      RECT 42.891 170.772 42.963 170.796 ;
    END
  END r0_addr_in[5]
  PIN r0_addr_in[6]
    DIRECTION INPUT ;
    USE SIGNAL ;
    SHAPE ABUTMENT ;
    PORT
      LAYER M4 ;
      RECT 42.891 175.380 42.963 175.404 ;
    END
  END r0_addr_in[6]
  PIN r0_addr_in[7]
    DIRECTION INPUT ;
    USE SIGNAL ;
    SHAPE ABUTMENT ;
    PORT
      LAYER M4 ;
      RECT 42.891 179.988 42.963 180.012 ;
    END
  END r0_addr_in[7]
  PIN r0_addr_in[8]
    DIRECTION INPUT ;
    USE SIGNAL ;
    SHAPE ABUTMENT ;
    PORT
      LAYER M4 ;
      RECT 42.891 184.596 42.963 184.620 ;
    END
  END r0_addr_in[8]
  PIN r0_addr_in[9]
    DIRECTION INPUT ;
    USE SIGNAL ;
    SHAPE ABUTMENT ;
    PORT
      LAYER M4 ;
      RECT 42.891 189.204 42.963 189.228 ;
    END
  END r0_addr_in[9]
  PIN rw0_we_in
    DIRECTION INPUT ;
    USE SIGNAL ;
    SHAPE ABUTMENT ;
    PORT
      LAYER M3 ;
      RECT 37.647 199.887 37.665 199.941 ;
    END
  END rw0_we_in
  PIN rw0_ce_in
    DIRECTION INPUT ;
    USE SIGNAL ;
    SHAPE ABUTMENT ;
    PORT
      LAYER M3 ;
      RECT 37.935 199.887 37.953 199.941 ;
    END
  END rw0_ce_in
  PIN rw0_clk
    DIRECTION INPUT ;
    USE SIGNAL ;
    SHAPE ABUTMENT ;
    PORT
      LAYER M3 ;
      RECT 38.223 199.887 38.241 199.941 ;
    END
  END rw0_clk
  PIN r0_ce_in
    DIRECTION INPUT ;
    USE SIGNAL ;
    SHAPE ABUTMENT ;
    PORT
      LAYER M3 ;
      RECT 38.511 199.887 38.529 199.941 ;
    END
  END r0_ce_in
  PIN r0_clk
    DIRECTION INPUT ;
    USE SIGNAL ;
    SHAPE ABUTMENT ;
    PORT
      LAYER M3 ;
      RECT 38.799 199.887 38.817 199.941 ;
    END
  END r0_clk
  PIN VSS
    DIRECTION INOUT ;
    USE GROUND ;
    PORT
      LAYER M4 ;
      RECT 0.216 0.240 42.747 0.336 ;
      RECT 0.216 1.008 42.747 1.104 ;
      RECT 0.216 1.776 42.747 1.872 ;
      RECT 0.216 2.544 42.747 2.640 ;
      RECT 0.216 3.312 42.747 3.408 ;
      RECT 0.216 4.080 42.747 4.176 ;
      RECT 0.216 4.848 42.747 4.944 ;
      RECT 0.216 5.616 42.747 5.712 ;
      RECT 0.216 6.384 42.747 6.480 ;
      RECT 0.216 7.152 42.747 7.248 ;
      RECT 0.216 7.920 42.747 8.016 ;
      RECT 0.216 8.688 42.747 8.784 ;
      RECT 0.216 9.456 42.747 9.552 ;
      RECT 0.216 10.224 42.747 10.320 ;
      RECT 0.216 10.992 42.747 11.088 ;
      RECT 0.216 11.760 42.747 11.856 ;
      RECT 0.216 12.528 42.747 12.624 ;
      RECT 0.216 13.296 42.747 13.392 ;
      RECT 0.216 14.064 42.747 14.160 ;
      RECT 0.216 14.832 42.747 14.928 ;
      RECT 0.216 15.600 42.747 15.696 ;
      RECT 0.216 16.368 42.747 16.464 ;
      RECT 0.216 17.136 42.747 17.232 ;
      RECT 0.216 17.904 42.747 18.000 ;
      RECT 0.216 18.672 42.747 18.768 ;
      RECT 0.216 19.440 42.747 19.536 ;
      RECT 0.216 20.208 42.747 20.304 ;
      RECT 0.216 20.976 42.747 21.072 ;
      RECT 0.216 21.744 42.747 21.840 ;
      RECT 0.216 22.512 42.747 22.608 ;
      RECT 0.216 23.280 42.747 23.376 ;
      RECT 0.216 24.048 42.747 24.144 ;
      RECT 0.216 24.816 42.747 24.912 ;
      RECT 0.216 25.584 42.747 25.680 ;
      RECT 0.216 26.352 42.747 26.448 ;
      RECT 0.216 27.120 42.747 27.216 ;
      RECT 0.216 27.888 42.747 27.984 ;
      RECT 0.216 28.656 42.747 28.752 ;
      RECT 0.216 29.424 42.747 29.520 ;
      RECT 0.216 30.192 42.747 30.288 ;
      RECT 0.216 30.960 42.747 31.056 ;
      RECT 0.216 31.728 42.747 31.824 ;
      RECT 0.216 32.496 42.747 32.592 ;
      RECT 0.216 33.264 42.747 33.360 ;
      RECT 0.216 34.032 42.747 34.128 ;
      RECT 0.216 34.800 42.747 34.896 ;
      RECT 0.216 35.568 42.747 35.664 ;
      RECT 0.216 36.336 42.747 36.432 ;
      RECT 0.216 37.104 42.747 37.200 ;
      RECT 0.216 37.872 42.747 37.968 ;
      RECT 0.216 38.640 42.747 38.736 ;
      RECT 0.216 39.408 42.747 39.504 ;
      RECT 0.216 40.176 42.747 40.272 ;
      RECT 0.216 40.944 42.747 41.040 ;
      RECT 0.216 41.712 42.747 41.808 ;
      RECT 0.216 42.480 42.747 42.576 ;
      RECT 0.216 43.248 42.747 43.344 ;
      RECT 0.216 44.016 42.747 44.112 ;
      RECT 0.216 44.784 42.747 44.880 ;
      RECT 0.216 45.552 42.747 45.648 ;
      RECT 0.216 46.320 42.747 46.416 ;
      RECT 0.216 47.088 42.747 47.184 ;
      RECT 0.216 47.856 42.747 47.952 ;
      RECT 0.216 48.624 42.747 48.720 ;
      RECT 0.216 49.392 42.747 49.488 ;
      RECT 0.216 50.160 42.747 50.256 ;
      RECT 0.216 50.928 42.747 51.024 ;
      RECT 0.216 51.696 42.747 51.792 ;
      RECT 0.216 52.464 42.747 52.560 ;
      RECT 0.216 53.232 42.747 53.328 ;
      RECT 0.216 54.000 42.747 54.096 ;
      RECT 0.216 54.768 42.747 54.864 ;
      RECT 0.216 55.536 42.747 55.632 ;
      RECT 0.216 56.304 42.747 56.400 ;
      RECT 0.216 57.072 42.747 57.168 ;
      RECT 0.216 57.840 42.747 57.936 ;
      RECT 0.216 58.608 42.747 58.704 ;
      RECT 0.216 59.376 42.747 59.472 ;
      RECT 0.216 60.144 42.747 60.240 ;
      RECT 0.216 60.912 42.747 61.008 ;
      RECT 0.216 61.680 42.747 61.776 ;
      RECT 0.216 62.448 42.747 62.544 ;
      RECT 0.216 63.216 42.747 63.312 ;
      RECT 0.216 63.984 42.747 64.080 ;
      RECT 0.216 64.752 42.747 64.848 ;
      RECT 0.216 65.520 42.747 65.616 ;
      RECT 0.216 66.288 42.747 66.384 ;
      RECT 0.216 67.056 42.747 67.152 ;
      RECT 0.216 67.824 42.747 67.920 ;
      RECT 0.216 68.592 42.747 68.688 ;
      RECT 0.216 69.360 42.747 69.456 ;
      RECT 0.216 70.128 42.747 70.224 ;
      RECT 0.216 70.896 42.747 70.992 ;
      RECT 0.216 71.664 42.747 71.760 ;
      RECT 0.216 72.432 42.747 72.528 ;
      RECT 0.216 73.200 42.747 73.296 ;
      RECT 0.216 73.968 42.747 74.064 ;
      RECT 0.216 74.736 42.747 74.832 ;
      RECT 0.216 75.504 42.747 75.600 ;
      RECT 0.216 76.272 42.747 76.368 ;
      RECT 0.216 77.040 42.747 77.136 ;
      RECT 0.216 77.808 42.747 77.904 ;
      RECT 0.216 78.576 42.747 78.672 ;
      RECT 0.216 79.344 42.747 79.440 ;
      RECT 0.216 80.112 42.747 80.208 ;
      RECT 0.216 80.880 42.747 80.976 ;
      RECT 0.216 81.648 42.747 81.744 ;
      RECT 0.216 82.416 42.747 82.512 ;
      RECT 0.216 83.184 42.747 83.280 ;
      RECT 0.216 83.952 42.747 84.048 ;
      RECT 0.216 84.720 42.747 84.816 ;
      RECT 0.216 85.488 42.747 85.584 ;
      RECT 0.216 86.256 42.747 86.352 ;
      RECT 0.216 87.024 42.747 87.120 ;
      RECT 0.216 87.792 42.747 87.888 ;
      RECT 0.216 88.560 42.747 88.656 ;
      RECT 0.216 89.328 42.747 89.424 ;
      RECT 0.216 90.096 42.747 90.192 ;
      RECT 0.216 90.864 42.747 90.960 ;
      RECT 0.216 91.632 42.747 91.728 ;
      RECT 0.216 92.400 42.747 92.496 ;
      RECT 0.216 93.168 42.747 93.264 ;
      RECT 0.216 93.936 42.747 94.032 ;
      RECT 0.216 94.704 42.747 94.800 ;
      RECT 0.216 95.472 42.747 95.568 ;
      RECT 0.216 96.240 42.747 96.336 ;
      RECT 0.216 97.008 42.747 97.104 ;
      RECT 0.216 97.776 42.747 97.872 ;
      RECT 0.216 98.544 42.747 98.640 ;
      RECT 0.216 99.312 42.747 99.408 ;
      RECT 0.216 100.080 42.747 100.176 ;
      RECT 0.216 100.848 42.747 100.944 ;
      RECT 0.216 101.616 42.747 101.712 ;
      RECT 0.216 102.384 42.747 102.480 ;
      RECT 0.216 103.152 42.747 103.248 ;
      RECT 0.216 103.920 42.747 104.016 ;
      RECT 0.216 104.688 42.747 104.784 ;
      RECT 0.216 105.456 42.747 105.552 ;
      RECT 0.216 106.224 42.747 106.320 ;
      RECT 0.216 106.992 42.747 107.088 ;
      RECT 0.216 107.760 42.747 107.856 ;
      RECT 0.216 108.528 42.747 108.624 ;
      RECT 0.216 109.296 42.747 109.392 ;
      RECT 0.216 110.064 42.747 110.160 ;
      RECT 0.216 110.832 42.747 110.928 ;
      RECT 0.216 111.600 42.747 111.696 ;
      RECT 0.216 112.368 42.747 112.464 ;
      RECT 0.216 113.136 42.747 113.232 ;
      RECT 0.216 113.904 42.747 114.000 ;
      RECT 0.216 114.672 42.747 114.768 ;
      RECT 0.216 115.440 42.747 115.536 ;
      RECT 0.216 116.208 42.747 116.304 ;
      RECT 0.216 116.976 42.747 117.072 ;
      RECT 0.216 117.744 42.747 117.840 ;
      RECT 0.216 118.512 42.747 118.608 ;
      RECT 0.216 119.280 42.747 119.376 ;
      RECT 0.216 120.048 42.747 120.144 ;
      RECT 0.216 120.816 42.747 120.912 ;
      RECT 0.216 121.584 42.747 121.680 ;
      RECT 0.216 122.352 42.747 122.448 ;
      RECT 0.216 123.120 42.747 123.216 ;
      RECT 0.216 123.888 42.747 123.984 ;
      RECT 0.216 124.656 42.747 124.752 ;
      RECT 0.216 125.424 42.747 125.520 ;
      RECT 0.216 126.192 42.747 126.288 ;
      RECT 0.216 126.960 42.747 127.056 ;
      RECT 0.216 127.728 42.747 127.824 ;
      RECT 0.216 128.496 42.747 128.592 ;
      RECT 0.216 129.264 42.747 129.360 ;
      RECT 0.216 130.032 42.747 130.128 ;
      RECT 0.216 130.800 42.747 130.896 ;
      RECT 0.216 131.568 42.747 131.664 ;
      RECT 0.216 132.336 42.747 132.432 ;
      RECT 0.216 133.104 42.747 133.200 ;
      RECT 0.216 133.872 42.747 133.968 ;
      RECT 0.216 134.640 42.747 134.736 ;
      RECT 0.216 135.408 42.747 135.504 ;
      RECT 0.216 136.176 42.747 136.272 ;
      RECT 0.216 136.944 42.747 137.040 ;
      RECT 0.216 137.712 42.747 137.808 ;
      RECT 0.216 138.480 42.747 138.576 ;
      RECT 0.216 139.248 42.747 139.344 ;
      RECT 0.216 140.016 42.747 140.112 ;
      RECT 0.216 140.784 42.747 140.880 ;
      RECT 0.216 141.552 42.747 141.648 ;
      RECT 0.216 142.320 42.747 142.416 ;
      RECT 0.216 143.088 42.747 143.184 ;
      RECT 0.216 143.856 42.747 143.952 ;
      RECT 0.216 144.624 42.747 144.720 ;
      RECT 0.216 145.392 42.747 145.488 ;
      RECT 0.216 146.160 42.747 146.256 ;
      RECT 0.216 146.928 42.747 147.024 ;
      RECT 0.216 147.696 42.747 147.792 ;
      RECT 0.216 148.464 42.747 148.560 ;
      RECT 0.216 149.232 42.747 149.328 ;
      RECT 0.216 150.000 42.747 150.096 ;
      RECT 0.216 150.768 42.747 150.864 ;
      RECT 0.216 151.536 42.747 151.632 ;
      RECT 0.216 152.304 42.747 152.400 ;
      RECT 0.216 153.072 42.747 153.168 ;
      RECT 0.216 153.840 42.747 153.936 ;
      RECT 0.216 154.608 42.747 154.704 ;
      RECT 0.216 155.376 42.747 155.472 ;
      RECT 0.216 156.144 42.747 156.240 ;
      RECT 0.216 156.912 42.747 157.008 ;
      RECT 0.216 157.680 42.747 157.776 ;
      RECT 0.216 158.448 42.747 158.544 ;
      RECT 0.216 159.216 42.747 159.312 ;
      RECT 0.216 159.984 42.747 160.080 ;
      RECT 0.216 160.752 42.747 160.848 ;
      RECT 0.216 161.520 42.747 161.616 ;
      RECT 0.216 162.288 42.747 162.384 ;
      RECT 0.216 163.056 42.747 163.152 ;
      RECT 0.216 163.824 42.747 163.920 ;
      RECT 0.216 164.592 42.747 164.688 ;
      RECT 0.216 165.360 42.747 165.456 ;
      RECT 0.216 166.128 42.747 166.224 ;
      RECT 0.216 166.896 42.747 166.992 ;
      RECT 0.216 167.664 42.747 167.760 ;
      RECT 0.216 168.432 42.747 168.528 ;
      RECT 0.216 169.200 42.747 169.296 ;
      RECT 0.216 169.968 42.747 170.064 ;
      RECT 0.216 170.736 42.747 170.832 ;
      RECT 0.216 171.504 42.747 171.600 ;
      RECT 0.216 172.272 42.747 172.368 ;
      RECT 0.216 173.040 42.747 173.136 ;
      RECT 0.216 173.808 42.747 173.904 ;
      RECT 0.216 174.576 42.747 174.672 ;
      RECT 0.216 175.344 42.747 175.440 ;
      RECT 0.216 176.112 42.747 176.208 ;
      RECT 0.216 176.880 42.747 176.976 ;
      RECT 0.216 177.648 42.747 177.744 ;
      RECT 0.216 178.416 42.747 178.512 ;
      RECT 0.216 179.184 42.747 179.280 ;
      RECT 0.216 179.952 42.747 180.048 ;
      RECT 0.216 180.720 42.747 180.816 ;
      RECT 0.216 181.488 42.747 181.584 ;
      RECT 0.216 182.256 42.747 182.352 ;
      RECT 0.216 183.024 42.747 183.120 ;
      RECT 0.216 183.792 42.747 183.888 ;
      RECT 0.216 184.560 42.747 184.656 ;
      RECT 0.216 185.328 42.747 185.424 ;
      RECT 0.216 186.096 42.747 186.192 ;
      RECT 0.216 186.864 42.747 186.960 ;
      RECT 0.216 187.632 42.747 187.728 ;
      RECT 0.216 188.400 42.747 188.496 ;
      RECT 0.216 189.168 42.747 189.264 ;
      RECT 0.216 189.936 42.747 190.032 ;
      RECT 0.216 190.704 42.747 190.800 ;
      RECT 0.216 191.472 42.747 191.568 ;
      RECT 0.216 192.240 42.747 192.336 ;
      RECT 0.216 193.008 42.747 193.104 ;
      RECT 0.216 193.776 42.747 193.872 ;
      RECT 0.216 194.544 42.747 194.640 ;
      RECT 0.216 195.312 42.747 195.408 ;
      RECT 0.216 196.080 42.747 196.176 ;
      RECT 0.216 196.848 42.747 196.944 ;
      RECT 0.216 197.616 42.747 197.712 ;
      RECT 0.216 198.384 42.747 198.480 ;
      RECT 0.216 199.152 42.747 199.248 ;
    END
  END VSS
  PIN VDD
    DIRECTION INOUT ;
    USE POWER ;
    PORT
      LAYER M4 ;
      RECT 0.216 0.240 42.747 0.336 ;
      RECT 0.216 1.008 42.747 1.104 ;
      RECT 0.216 1.776 42.747 1.872 ;
      RECT 0.216 2.544 42.747 2.640 ;
      RECT 0.216 3.312 42.747 3.408 ;
      RECT 0.216 4.080 42.747 4.176 ;
      RECT 0.216 4.848 42.747 4.944 ;
      RECT 0.216 5.616 42.747 5.712 ;
      RECT 0.216 6.384 42.747 6.480 ;
      RECT 0.216 7.152 42.747 7.248 ;
      RECT 0.216 7.920 42.747 8.016 ;
      RECT 0.216 8.688 42.747 8.784 ;
      RECT 0.216 9.456 42.747 9.552 ;
      RECT 0.216 10.224 42.747 10.320 ;
      RECT 0.216 10.992 42.747 11.088 ;
      RECT 0.216 11.760 42.747 11.856 ;
      RECT 0.216 12.528 42.747 12.624 ;
      RECT 0.216 13.296 42.747 13.392 ;
      RECT 0.216 14.064 42.747 14.160 ;
      RECT 0.216 14.832 42.747 14.928 ;
      RECT 0.216 15.600 42.747 15.696 ;
      RECT 0.216 16.368 42.747 16.464 ;
      RECT 0.216 17.136 42.747 17.232 ;
      RECT 0.216 17.904 42.747 18.000 ;
      RECT 0.216 18.672 42.747 18.768 ;
      RECT 0.216 19.440 42.747 19.536 ;
      RECT 0.216 20.208 42.747 20.304 ;
      RECT 0.216 20.976 42.747 21.072 ;
      RECT 0.216 21.744 42.747 21.840 ;
      RECT 0.216 22.512 42.747 22.608 ;
      RECT 0.216 23.280 42.747 23.376 ;
      RECT 0.216 24.048 42.747 24.144 ;
      RECT 0.216 24.816 42.747 24.912 ;
      RECT 0.216 25.584 42.747 25.680 ;
      RECT 0.216 26.352 42.747 26.448 ;
      RECT 0.216 27.120 42.747 27.216 ;
      RECT 0.216 27.888 42.747 27.984 ;
      RECT 0.216 28.656 42.747 28.752 ;
      RECT 0.216 29.424 42.747 29.520 ;
      RECT 0.216 30.192 42.747 30.288 ;
      RECT 0.216 30.960 42.747 31.056 ;
      RECT 0.216 31.728 42.747 31.824 ;
      RECT 0.216 32.496 42.747 32.592 ;
      RECT 0.216 33.264 42.747 33.360 ;
      RECT 0.216 34.032 42.747 34.128 ;
      RECT 0.216 34.800 42.747 34.896 ;
      RECT 0.216 35.568 42.747 35.664 ;
      RECT 0.216 36.336 42.747 36.432 ;
      RECT 0.216 37.104 42.747 37.200 ;
      RECT 0.216 37.872 42.747 37.968 ;
      RECT 0.216 38.640 42.747 38.736 ;
      RECT 0.216 39.408 42.747 39.504 ;
      RECT 0.216 40.176 42.747 40.272 ;
      RECT 0.216 40.944 42.747 41.040 ;
      RECT 0.216 41.712 42.747 41.808 ;
      RECT 0.216 42.480 42.747 42.576 ;
      RECT 0.216 43.248 42.747 43.344 ;
      RECT 0.216 44.016 42.747 44.112 ;
      RECT 0.216 44.784 42.747 44.880 ;
      RECT 0.216 45.552 42.747 45.648 ;
      RECT 0.216 46.320 42.747 46.416 ;
      RECT 0.216 47.088 42.747 47.184 ;
      RECT 0.216 47.856 42.747 47.952 ;
      RECT 0.216 48.624 42.747 48.720 ;
      RECT 0.216 49.392 42.747 49.488 ;
      RECT 0.216 50.160 42.747 50.256 ;
      RECT 0.216 50.928 42.747 51.024 ;
      RECT 0.216 51.696 42.747 51.792 ;
      RECT 0.216 52.464 42.747 52.560 ;
      RECT 0.216 53.232 42.747 53.328 ;
      RECT 0.216 54.000 42.747 54.096 ;
      RECT 0.216 54.768 42.747 54.864 ;
      RECT 0.216 55.536 42.747 55.632 ;
      RECT 0.216 56.304 42.747 56.400 ;
      RECT 0.216 57.072 42.747 57.168 ;
      RECT 0.216 57.840 42.747 57.936 ;
      RECT 0.216 58.608 42.747 58.704 ;
      RECT 0.216 59.376 42.747 59.472 ;
      RECT 0.216 60.144 42.747 60.240 ;
      RECT 0.216 60.912 42.747 61.008 ;
      RECT 0.216 61.680 42.747 61.776 ;
      RECT 0.216 62.448 42.747 62.544 ;
      RECT 0.216 63.216 42.747 63.312 ;
      RECT 0.216 63.984 42.747 64.080 ;
      RECT 0.216 64.752 42.747 64.848 ;
      RECT 0.216 65.520 42.747 65.616 ;
      RECT 0.216 66.288 42.747 66.384 ;
      RECT 0.216 67.056 42.747 67.152 ;
      RECT 0.216 67.824 42.747 67.920 ;
      RECT 0.216 68.592 42.747 68.688 ;
      RECT 0.216 69.360 42.747 69.456 ;
      RECT 0.216 70.128 42.747 70.224 ;
      RECT 0.216 70.896 42.747 70.992 ;
      RECT 0.216 71.664 42.747 71.760 ;
      RECT 0.216 72.432 42.747 72.528 ;
      RECT 0.216 73.200 42.747 73.296 ;
      RECT 0.216 73.968 42.747 74.064 ;
      RECT 0.216 74.736 42.747 74.832 ;
      RECT 0.216 75.504 42.747 75.600 ;
      RECT 0.216 76.272 42.747 76.368 ;
      RECT 0.216 77.040 42.747 77.136 ;
      RECT 0.216 77.808 42.747 77.904 ;
      RECT 0.216 78.576 42.747 78.672 ;
      RECT 0.216 79.344 42.747 79.440 ;
      RECT 0.216 80.112 42.747 80.208 ;
      RECT 0.216 80.880 42.747 80.976 ;
      RECT 0.216 81.648 42.747 81.744 ;
      RECT 0.216 82.416 42.747 82.512 ;
      RECT 0.216 83.184 42.747 83.280 ;
      RECT 0.216 83.952 42.747 84.048 ;
      RECT 0.216 84.720 42.747 84.816 ;
      RECT 0.216 85.488 42.747 85.584 ;
      RECT 0.216 86.256 42.747 86.352 ;
      RECT 0.216 87.024 42.747 87.120 ;
      RECT 0.216 87.792 42.747 87.888 ;
      RECT 0.216 88.560 42.747 88.656 ;
      RECT 0.216 89.328 42.747 89.424 ;
      RECT 0.216 90.096 42.747 90.192 ;
      RECT 0.216 90.864 42.747 90.960 ;
      RECT 0.216 91.632 42.747 91.728 ;
      RECT 0.216 92.400 42.747 92.496 ;
      RECT 0.216 93.168 42.747 93.264 ;
      RECT 0.216 93.936 42.747 94.032 ;
      RECT 0.216 94.704 42.747 94.800 ;
      RECT 0.216 95.472 42.747 95.568 ;
      RECT 0.216 96.240 42.747 96.336 ;
      RECT 0.216 97.008 42.747 97.104 ;
      RECT 0.216 97.776 42.747 97.872 ;
      RECT 0.216 98.544 42.747 98.640 ;
      RECT 0.216 99.312 42.747 99.408 ;
      RECT 0.216 100.080 42.747 100.176 ;
      RECT 0.216 100.848 42.747 100.944 ;
      RECT 0.216 101.616 42.747 101.712 ;
      RECT 0.216 102.384 42.747 102.480 ;
      RECT 0.216 103.152 42.747 103.248 ;
      RECT 0.216 103.920 42.747 104.016 ;
      RECT 0.216 104.688 42.747 104.784 ;
      RECT 0.216 105.456 42.747 105.552 ;
      RECT 0.216 106.224 42.747 106.320 ;
      RECT 0.216 106.992 42.747 107.088 ;
      RECT 0.216 107.760 42.747 107.856 ;
      RECT 0.216 108.528 42.747 108.624 ;
      RECT 0.216 109.296 42.747 109.392 ;
      RECT 0.216 110.064 42.747 110.160 ;
      RECT 0.216 110.832 42.747 110.928 ;
      RECT 0.216 111.600 42.747 111.696 ;
      RECT 0.216 112.368 42.747 112.464 ;
      RECT 0.216 113.136 42.747 113.232 ;
      RECT 0.216 113.904 42.747 114.000 ;
      RECT 0.216 114.672 42.747 114.768 ;
      RECT 0.216 115.440 42.747 115.536 ;
      RECT 0.216 116.208 42.747 116.304 ;
      RECT 0.216 116.976 42.747 117.072 ;
      RECT 0.216 117.744 42.747 117.840 ;
      RECT 0.216 118.512 42.747 118.608 ;
      RECT 0.216 119.280 42.747 119.376 ;
      RECT 0.216 120.048 42.747 120.144 ;
      RECT 0.216 120.816 42.747 120.912 ;
      RECT 0.216 121.584 42.747 121.680 ;
      RECT 0.216 122.352 42.747 122.448 ;
      RECT 0.216 123.120 42.747 123.216 ;
      RECT 0.216 123.888 42.747 123.984 ;
      RECT 0.216 124.656 42.747 124.752 ;
      RECT 0.216 125.424 42.747 125.520 ;
      RECT 0.216 126.192 42.747 126.288 ;
      RECT 0.216 126.960 42.747 127.056 ;
      RECT 0.216 127.728 42.747 127.824 ;
      RECT 0.216 128.496 42.747 128.592 ;
      RECT 0.216 129.264 42.747 129.360 ;
      RECT 0.216 130.032 42.747 130.128 ;
      RECT 0.216 130.800 42.747 130.896 ;
      RECT 0.216 131.568 42.747 131.664 ;
      RECT 0.216 132.336 42.747 132.432 ;
      RECT 0.216 133.104 42.747 133.200 ;
      RECT 0.216 133.872 42.747 133.968 ;
      RECT 0.216 134.640 42.747 134.736 ;
      RECT 0.216 135.408 42.747 135.504 ;
      RECT 0.216 136.176 42.747 136.272 ;
      RECT 0.216 136.944 42.747 137.040 ;
      RECT 0.216 137.712 42.747 137.808 ;
      RECT 0.216 138.480 42.747 138.576 ;
      RECT 0.216 139.248 42.747 139.344 ;
      RECT 0.216 140.016 42.747 140.112 ;
      RECT 0.216 140.784 42.747 140.880 ;
      RECT 0.216 141.552 42.747 141.648 ;
      RECT 0.216 142.320 42.747 142.416 ;
      RECT 0.216 143.088 42.747 143.184 ;
      RECT 0.216 143.856 42.747 143.952 ;
      RECT 0.216 144.624 42.747 144.720 ;
      RECT 0.216 145.392 42.747 145.488 ;
      RECT 0.216 146.160 42.747 146.256 ;
      RECT 0.216 146.928 42.747 147.024 ;
      RECT 0.216 147.696 42.747 147.792 ;
      RECT 0.216 148.464 42.747 148.560 ;
      RECT 0.216 149.232 42.747 149.328 ;
      RECT 0.216 150.000 42.747 150.096 ;
      RECT 0.216 150.768 42.747 150.864 ;
      RECT 0.216 151.536 42.747 151.632 ;
      RECT 0.216 152.304 42.747 152.400 ;
      RECT 0.216 153.072 42.747 153.168 ;
      RECT 0.216 153.840 42.747 153.936 ;
      RECT 0.216 154.608 42.747 154.704 ;
      RECT 0.216 155.376 42.747 155.472 ;
      RECT 0.216 156.144 42.747 156.240 ;
      RECT 0.216 156.912 42.747 157.008 ;
      RECT 0.216 157.680 42.747 157.776 ;
      RECT 0.216 158.448 42.747 158.544 ;
      RECT 0.216 159.216 42.747 159.312 ;
      RECT 0.216 159.984 42.747 160.080 ;
      RECT 0.216 160.752 42.747 160.848 ;
      RECT 0.216 161.520 42.747 161.616 ;
      RECT 0.216 162.288 42.747 162.384 ;
      RECT 0.216 163.056 42.747 163.152 ;
      RECT 0.216 163.824 42.747 163.920 ;
      RECT 0.216 164.592 42.747 164.688 ;
      RECT 0.216 165.360 42.747 165.456 ;
      RECT 0.216 166.128 42.747 166.224 ;
      RECT 0.216 166.896 42.747 166.992 ;
      RECT 0.216 167.664 42.747 167.760 ;
      RECT 0.216 168.432 42.747 168.528 ;
      RECT 0.216 169.200 42.747 169.296 ;
      RECT 0.216 169.968 42.747 170.064 ;
      RECT 0.216 170.736 42.747 170.832 ;
      RECT 0.216 171.504 42.747 171.600 ;
      RECT 0.216 172.272 42.747 172.368 ;
      RECT 0.216 173.040 42.747 173.136 ;
      RECT 0.216 173.808 42.747 173.904 ;
      RECT 0.216 174.576 42.747 174.672 ;
      RECT 0.216 175.344 42.747 175.440 ;
      RECT 0.216 176.112 42.747 176.208 ;
      RECT 0.216 176.880 42.747 176.976 ;
      RECT 0.216 177.648 42.747 177.744 ;
      RECT 0.216 178.416 42.747 178.512 ;
      RECT 0.216 179.184 42.747 179.280 ;
      RECT 0.216 179.952 42.747 180.048 ;
      RECT 0.216 180.720 42.747 180.816 ;
      RECT 0.216 181.488 42.747 181.584 ;
      RECT 0.216 182.256 42.747 182.352 ;
      RECT 0.216 183.024 42.747 183.120 ;
      RECT 0.216 183.792 42.747 183.888 ;
      RECT 0.216 184.560 42.747 184.656 ;
      RECT 0.216 185.328 42.747 185.424 ;
      RECT 0.216 186.096 42.747 186.192 ;
      RECT 0.216 186.864 42.747 186.960 ;
      RECT 0.216 187.632 42.747 187.728 ;
      RECT 0.216 188.400 42.747 188.496 ;
      RECT 0.216 189.168 42.747 189.264 ;
      RECT 0.216 189.936 42.747 190.032 ;
      RECT 0.216 190.704 42.747 190.800 ;
      RECT 0.216 191.472 42.747 191.568 ;
      RECT 0.216 192.240 42.747 192.336 ;
      RECT 0.216 193.008 42.747 193.104 ;
      RECT 0.216 193.776 42.747 193.872 ;
      RECT 0.216 194.544 42.747 194.640 ;
      RECT 0.216 195.312 42.747 195.408 ;
      RECT 0.216 196.080 42.747 196.176 ;
      RECT 0.216 196.848 42.747 196.944 ;
      RECT 0.216 197.616 42.747 197.712 ;
      RECT 0.216 198.384 42.747 198.480 ;
      RECT 0.216 199.152 42.747 199.248 ;
    END
  END VDD
  OBS
    LAYER M1 ;
    RECT 0 0 42.963 199.941 ;
    LAYER M2 ;
    RECT 0 0 42.963 199.941 ;
    LAYER M3 ;
    RECT 0 0 42.963 199.941 ;
    LAYER M4 ;
    RECT 0 0 42.963 199.941 ;
  END
END fakeram_1rw1r_130w1024d_sram

END LIBRARY
